VERSION 5.7 ;
  NOWIREEXTENSIONATPIN ON ;
  DIVIDERCHAR "/" ;
  BUSBITCHARS "[]" ;
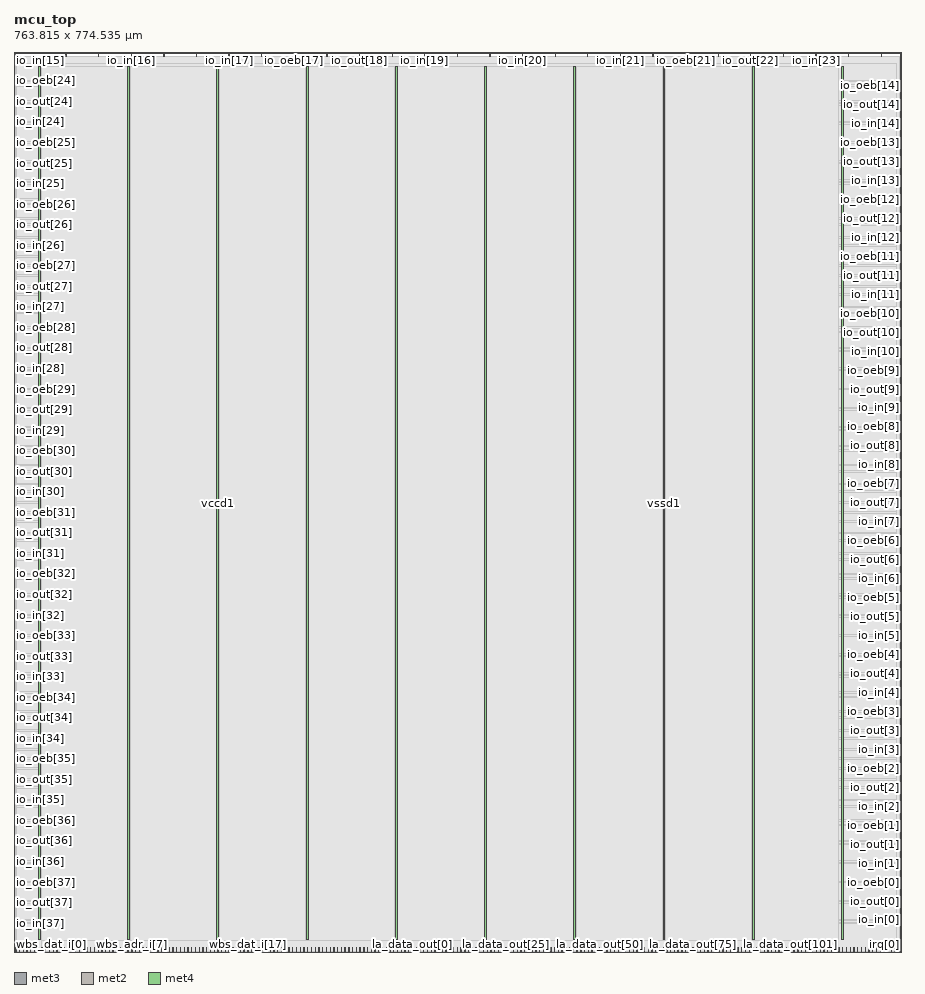
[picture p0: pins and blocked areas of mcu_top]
MACRO mcu_top
  CLASS BLOCK ;
  FOREIGN mcu_top ;
  ORIGIN 0.000 0.000 ;
  SIZE 763.815 BY 774.535 ;
  PIN io_in[0]
    DIRECTION INPUT ;
    USE SIGNAL ;
    PORT
      LAYER met3 ;
        RECT 759.815 27.240 763.815 27.840 ;
    END
  END io_in[0]
  PIN io_in[10]
    DIRECTION INPUT ;
    USE SIGNAL ;
    ANTENNAGATEAREA 0.213000 ;
    PORT
      LAYER met3 ;
        RECT 759.815 516.840 763.815 517.440 ;
    END
  END io_in[10]
  PIN io_in[11]
    DIRECTION INPUT ;
    USE SIGNAL ;
    ANTENNAGATEAREA 0.247500 ;
    PORT
      LAYER met3 ;
        RECT 759.815 565.800 763.815 566.400 ;
    END
  END io_in[11]
  PIN io_in[12]
    DIRECTION INPUT ;
    USE SIGNAL ;
    ANTENNAGATEAREA 0.247500 ;
    PORT
      LAYER met3 ;
        RECT 759.815 614.760 763.815 615.360 ;
    END
  END io_in[12]
  PIN io_in[13]
    DIRECTION INPUT ;
    USE SIGNAL ;
    ANTENNAGATEAREA 0.247500 ;
    PORT
      LAYER met3 ;
        RECT 759.815 663.720 763.815 664.320 ;
    END
  END io_in[13]
  PIN io_in[14]
    DIRECTION INPUT ;
    USE SIGNAL ;
    ANTENNAGATEAREA 0.247500 ;
    PORT
      LAYER met3 ;
        RECT 759.815 712.680 763.815 713.280 ;
    END
  END io_in[14]
  PIN io_in[15]
    DIRECTION INPUT ;
    USE SIGNAL ;
    ANTENNAGATEAREA 0.247500 ;
    PORT
      LAYER met2 ;
        RECT 16.650 770.535 16.930 774.535 ;
    END
  END io_in[15]
  PIN io_in[16]
    DIRECTION INPUT ;
    USE SIGNAL ;
    ANTENNAGATEAREA 0.247500 ;
    PORT
      LAYER met2 ;
        RECT 100.830 770.535 101.110 774.535 ;
    END
  END io_in[16]
  PIN io_in[17]
    DIRECTION INPUT ;
    USE SIGNAL ;
    ANTENNAGATEAREA 0.247500 ;
    PORT
      LAYER met2 ;
        RECT 185.010 770.535 185.290 774.535 ;
    END
  END io_in[17]
  PIN io_in[18]
    DIRECTION INPUT ;
    USE SIGNAL ;
    ANTENNAGATEAREA 0.213000 ;
    PORT
      LAYER met2 ;
        RECT 269.190 770.535 269.470 774.535 ;
    END
  END io_in[18]
  PIN io_in[19]
    DIRECTION INPUT ;
    USE SIGNAL ;
    ANTENNAGATEAREA 0.213000 ;
    PORT
      LAYER met2 ;
        RECT 353.370 770.535 353.650 774.535 ;
    END
  END io_in[19]
  PIN io_in[1]
    DIRECTION INPUT ;
    USE SIGNAL ;
    PORT
      LAYER met3 ;
        RECT 759.815 76.200 763.815 76.800 ;
    END
  END io_in[1]
  PIN io_in[20]
    DIRECTION INPUT ;
    USE SIGNAL ;
    ANTENNAGATEAREA 0.213000 ;
    PORT
      LAYER met2 ;
        RECT 437.550 770.535 437.830 774.535 ;
    END
  END io_in[20]
  PIN io_in[21]
    DIRECTION INPUT ;
    USE SIGNAL ;
    ANTENNAGATEAREA 0.213000 ;
    PORT
      LAYER met2 ;
        RECT 521.730 770.535 522.010 774.535 ;
    END
  END io_in[21]
  PIN io_in[22]
    DIRECTION INPUT ;
    USE SIGNAL ;
    ANTENNAGATEAREA 0.247500 ;
    PORT
      LAYER met2 ;
        RECT 605.910 770.535 606.190 774.535 ;
    END
  END io_in[22]
  PIN io_in[23]
    DIRECTION INPUT ;
    USE SIGNAL ;
    ANTENNAGATEAREA 0.247500 ;
    PORT
      LAYER met2 ;
        RECT 690.090 770.535 690.370 774.535 ;
    END
  END io_in[23]
  PIN io_in[24]
    DIRECTION INPUT ;
    USE SIGNAL ;
    ANTENNAGATEAREA 0.247500 ;
    PORT
      LAYER met3 ;
        RECT 0.000 714.040 4.000 714.640 ;
    END
  END io_in[24]
  PIN io_in[25]
    DIRECTION INPUT ;
    USE SIGNAL ;
    ANTENNAGATEAREA 0.247500 ;
    PORT
      LAYER met3 ;
        RECT 0.000 661.000 4.000 661.600 ;
    END
  END io_in[25]
  PIN io_in[26]
    DIRECTION INPUT ;
    USE SIGNAL ;
    PORT
      LAYER met3 ;
        RECT 0.000 607.960 4.000 608.560 ;
    END
  END io_in[26]
  PIN io_in[27]
    DIRECTION INPUT ;
    USE SIGNAL ;
    PORT
      LAYER met3 ;
        RECT 0.000 554.920 4.000 555.520 ;
    END
  END io_in[27]
  PIN io_in[28]
    DIRECTION INPUT ;
    USE SIGNAL ;
    PORT
      LAYER met3 ;
        RECT 0.000 501.880 4.000 502.480 ;
    END
  END io_in[28]
  PIN io_in[29]
    DIRECTION INPUT ;
    USE SIGNAL ;
    PORT
      LAYER met3 ;
        RECT 0.000 448.840 4.000 449.440 ;
    END
  END io_in[29]
  PIN io_in[2]
    DIRECTION INPUT ;
    USE SIGNAL ;
    PORT
      LAYER met3 ;
        RECT 759.815 125.160 763.815 125.760 ;
    END
  END io_in[2]
  PIN io_in[30]
    DIRECTION INPUT ;
    USE SIGNAL ;
    PORT
      LAYER met3 ;
        RECT 0.000 395.800 4.000 396.400 ;
    END
  END io_in[30]
  PIN io_in[31]
    DIRECTION INPUT ;
    USE SIGNAL ;
    PORT
      LAYER met3 ;
        RECT 0.000 342.760 4.000 343.360 ;
    END
  END io_in[31]
  PIN io_in[32]
    DIRECTION INPUT ;
    USE SIGNAL ;
    PORT
      LAYER met3 ;
        RECT 0.000 289.720 4.000 290.320 ;
    END
  END io_in[32]
  PIN io_in[33]
    DIRECTION INPUT ;
    USE SIGNAL ;
    PORT
      LAYER met3 ;
        RECT 0.000 236.680 4.000 237.280 ;
    END
  END io_in[33]
  PIN io_in[34]
    DIRECTION INPUT ;
    USE SIGNAL ;
    PORT
      LAYER met3 ;
        RECT 0.000 183.640 4.000 184.240 ;
    END
  END io_in[34]
  PIN io_in[35]
    DIRECTION INPUT ;
    USE SIGNAL ;
    PORT
      LAYER met3 ;
        RECT 0.000 130.600 4.000 131.200 ;
    END
  END io_in[35]
  PIN io_in[36]
    DIRECTION INPUT ;
    USE SIGNAL ;
    PORT
      LAYER met3 ;
        RECT 0.000 77.560 4.000 78.160 ;
    END
  END io_in[36]
  PIN io_in[37]
    DIRECTION INPUT ;
    USE SIGNAL ;
    PORT
      LAYER met3 ;
        RECT 0.000 24.520 4.000 25.120 ;
    END
  END io_in[37]
  PIN io_in[3]
    DIRECTION INPUT ;
    USE SIGNAL ;
    PORT
      LAYER met3 ;
        RECT 759.815 174.120 763.815 174.720 ;
    END
  END io_in[3]
  PIN io_in[4]
    DIRECTION INPUT ;
    USE SIGNAL ;
    PORT
      LAYER met3 ;
        RECT 759.815 223.080 763.815 223.680 ;
    END
  END io_in[4]
  PIN io_in[5]
    DIRECTION INPUT ;
    USE SIGNAL ;
    PORT
      LAYER met3 ;
        RECT 759.815 272.040 763.815 272.640 ;
    END
  END io_in[5]
  PIN io_in[6]
    DIRECTION INPUT ;
    USE SIGNAL ;
    PORT
      LAYER met3 ;
        RECT 759.815 321.000 763.815 321.600 ;
    END
  END io_in[6]
  PIN io_in[7]
    DIRECTION INPUT ;
    USE SIGNAL ;
    PORT
      LAYER met3 ;
        RECT 759.815 369.960 763.815 370.560 ;
    END
  END io_in[7]
  PIN io_in[8]
    DIRECTION INPUT ;
    USE SIGNAL ;
    PORT
      LAYER met3 ;
        RECT 759.815 418.920 763.815 419.520 ;
    END
  END io_in[8]
  PIN io_in[9]
    DIRECTION INPUT ;
    USE SIGNAL ;
    ANTENNAGATEAREA 0.247500 ;
    PORT
      LAYER met3 ;
        RECT 759.815 467.880 763.815 468.480 ;
    END
  END io_in[9]
  PIN io_oeb[0]
    DIRECTION OUTPUT ;
    USE SIGNAL ;
    PORT
      LAYER met3 ;
        RECT 759.815 59.880 763.815 60.480 ;
    END
  END io_oeb[0]
  PIN io_oeb[10]
    DIRECTION OUTPUT ;
    USE SIGNAL ;
    ANTENNADIFFAREA 2.673000 ;
    PORT
      LAYER met3 ;
        RECT 759.815 549.480 763.815 550.080 ;
    END
  END io_oeb[10]
  PIN io_oeb[11]
    DIRECTION OUTPUT ;
    USE SIGNAL ;
    ANTENNADIFFAREA 2.673000 ;
    PORT
      LAYER met3 ;
        RECT 759.815 598.440 763.815 599.040 ;
    END
  END io_oeb[11]
  PIN io_oeb[12]
    DIRECTION OUTPUT ;
    USE SIGNAL ;
    ANTENNADIFFAREA 2.673000 ;
    PORT
      LAYER met3 ;
        RECT 759.815 647.400 763.815 648.000 ;
    END
  END io_oeb[12]
  PIN io_oeb[13]
    DIRECTION OUTPUT ;
    USE SIGNAL ;
    ANTENNADIFFAREA 2.673000 ;
    PORT
      LAYER met3 ;
        RECT 759.815 696.360 763.815 696.960 ;
    END
  END io_oeb[13]
  PIN io_oeb[14]
    DIRECTION OUTPUT ;
    USE SIGNAL ;
    ANTENNADIFFAREA 2.673000 ;
    PORT
      LAYER met3 ;
        RECT 759.815 745.320 763.815 745.920 ;
    END
  END io_oeb[14]
  PIN io_oeb[15]
    DIRECTION OUTPUT ;
    USE SIGNAL ;
    ANTENNADIFFAREA 2.673000 ;
    PORT
      LAYER met2 ;
        RECT 72.770 770.535 73.050 774.535 ;
    END
  END io_oeb[15]
  PIN io_oeb[16]
    DIRECTION OUTPUT ;
    USE SIGNAL ;
    ANTENNADIFFAREA 2.673000 ;
    PORT
      LAYER met2 ;
        RECT 156.950 770.535 157.230 774.535 ;
    END
  END io_oeb[16]
  PIN io_oeb[17]
    DIRECTION OUTPUT ;
    USE SIGNAL ;
    ANTENNADIFFAREA 2.673000 ;
    PORT
      LAYER met2 ;
        RECT 241.130 770.535 241.410 774.535 ;
    END
  END io_oeb[17]
  PIN io_oeb[18]
    DIRECTION OUTPUT ;
    USE SIGNAL ;
    ANTENNADIFFAREA 2.673000 ;
    PORT
      LAYER met2 ;
        RECT 325.310 770.535 325.590 774.535 ;
    END
  END io_oeb[18]
  PIN io_oeb[19]
    DIRECTION OUTPUT ;
    USE SIGNAL ;
    ANTENNADIFFAREA 2.673000 ;
    PORT
      LAYER met2 ;
        RECT 409.490 770.535 409.770 774.535 ;
    END
  END io_oeb[19]
  PIN io_oeb[1]
    DIRECTION OUTPUT ;
    USE SIGNAL ;
    PORT
      LAYER met3 ;
        RECT 759.815 108.840 763.815 109.440 ;
    END
  END io_oeb[1]
  PIN io_oeb[20]
    DIRECTION OUTPUT ;
    USE SIGNAL ;
    ANTENNADIFFAREA 2.673000 ;
    PORT
      LAYER met2 ;
        RECT 493.670 770.535 493.950 774.535 ;
    END
  END io_oeb[20]
  PIN io_oeb[21]
    DIRECTION OUTPUT ;
    USE SIGNAL ;
    ANTENNADIFFAREA 2.673000 ;
    PORT
      LAYER met2 ;
        RECT 577.850 770.535 578.130 774.535 ;
    END
  END io_oeb[21]
  PIN io_oeb[22]
    DIRECTION OUTPUT ;
    USE SIGNAL ;
    ANTENNADIFFAREA 2.673000 ;
    PORT
      LAYER met2 ;
        RECT 662.030 770.535 662.310 774.535 ;
    END
  END io_oeb[22]
  PIN io_oeb[23]
    DIRECTION OUTPUT ;
    USE SIGNAL ;
    ANTENNADIFFAREA 2.673000 ;
    PORT
      LAYER met2 ;
        RECT 746.210 770.535 746.490 774.535 ;
    END
  END io_oeb[23]
  PIN io_oeb[24]
    DIRECTION OUTPUT ;
    USE SIGNAL ;
    ANTENNADIFFAREA 2.673000 ;
    PORT
      LAYER met3 ;
        RECT 0.000 749.400 4.000 750.000 ;
    END
  END io_oeb[24]
  PIN io_oeb[25]
    DIRECTION OUTPUT ;
    USE SIGNAL ;
    ANTENNADIFFAREA 2.673000 ;
    PORT
      LAYER met3 ;
        RECT 0.000 696.360 4.000 696.960 ;
    END
  END io_oeb[25]
  PIN io_oeb[26]
    DIRECTION OUTPUT ;
    USE SIGNAL ;
    PORT
      LAYER met3 ;
        RECT 0.000 643.320 4.000 643.920 ;
    END
  END io_oeb[26]
  PIN io_oeb[27]
    DIRECTION OUTPUT ;
    USE SIGNAL ;
    PORT
      LAYER met3 ;
        RECT 0.000 590.280 4.000 590.880 ;
    END
  END io_oeb[27]
  PIN io_oeb[28]
    DIRECTION OUTPUT ;
    USE SIGNAL ;
    PORT
      LAYER met3 ;
        RECT 0.000 537.240 4.000 537.840 ;
    END
  END io_oeb[28]
  PIN io_oeb[29]
    DIRECTION OUTPUT ;
    USE SIGNAL ;
    PORT
      LAYER met3 ;
        RECT 0.000 484.200 4.000 484.800 ;
    END
  END io_oeb[29]
  PIN io_oeb[2]
    DIRECTION OUTPUT ;
    USE SIGNAL ;
    PORT
      LAYER met3 ;
        RECT 759.815 157.800 763.815 158.400 ;
    END
  END io_oeb[2]
  PIN io_oeb[30]
    DIRECTION OUTPUT ;
    USE SIGNAL ;
    PORT
      LAYER met3 ;
        RECT 0.000 431.160 4.000 431.760 ;
    END
  END io_oeb[30]
  PIN io_oeb[31]
    DIRECTION OUTPUT ;
    USE SIGNAL ;
    PORT
      LAYER met3 ;
        RECT 0.000 378.120 4.000 378.720 ;
    END
  END io_oeb[31]
  PIN io_oeb[32]
    DIRECTION OUTPUT ;
    USE SIGNAL ;
    PORT
      LAYER met3 ;
        RECT 0.000 325.080 4.000 325.680 ;
    END
  END io_oeb[32]
  PIN io_oeb[33]
    DIRECTION OUTPUT ;
    USE SIGNAL ;
    PORT
      LAYER met3 ;
        RECT 0.000 272.040 4.000 272.640 ;
    END
  END io_oeb[33]
  PIN io_oeb[34]
    DIRECTION OUTPUT ;
    USE SIGNAL ;
    PORT
      LAYER met3 ;
        RECT 0.000 219.000 4.000 219.600 ;
    END
  END io_oeb[34]
  PIN io_oeb[35]
    DIRECTION OUTPUT ;
    USE SIGNAL ;
    PORT
      LAYER met3 ;
        RECT 0.000 165.960 4.000 166.560 ;
    END
  END io_oeb[35]
  PIN io_oeb[36]
    DIRECTION OUTPUT ;
    USE SIGNAL ;
    PORT
      LAYER met3 ;
        RECT 0.000 112.920 4.000 113.520 ;
    END
  END io_oeb[36]
  PIN io_oeb[37]
    DIRECTION OUTPUT ;
    USE SIGNAL ;
    PORT
      LAYER met3 ;
        RECT 0.000 59.880 4.000 60.480 ;
    END
  END io_oeb[37]
  PIN io_oeb[3]
    DIRECTION OUTPUT ;
    USE SIGNAL ;
    PORT
      LAYER met3 ;
        RECT 759.815 206.760 763.815 207.360 ;
    END
  END io_oeb[3]
  PIN io_oeb[4]
    DIRECTION OUTPUT ;
    USE SIGNAL ;
    PORT
      LAYER met3 ;
        RECT 759.815 255.720 763.815 256.320 ;
    END
  END io_oeb[4]
  PIN io_oeb[5]
    DIRECTION OUTPUT ;
    USE SIGNAL ;
    PORT
      LAYER met3 ;
        RECT 759.815 304.680 763.815 305.280 ;
    END
  END io_oeb[5]
  PIN io_oeb[6]
    DIRECTION OUTPUT ;
    USE SIGNAL ;
    PORT
      LAYER met3 ;
        RECT 759.815 353.640 763.815 354.240 ;
    END
  END io_oeb[6]
  PIN io_oeb[7]
    DIRECTION OUTPUT ;
    USE SIGNAL ;
    PORT
      LAYER met3 ;
        RECT 759.815 402.600 763.815 403.200 ;
    END
  END io_oeb[7]
  PIN io_oeb[8]
    DIRECTION OUTPUT ;
    USE SIGNAL ;
    PORT
      LAYER met3 ;
        RECT 759.815 451.560 763.815 452.160 ;
    END
  END io_oeb[8]
  PIN io_oeb[9]
    DIRECTION OUTPUT ;
    USE SIGNAL ;
    PORT
      LAYER met3 ;
        RECT 759.815 500.520 763.815 501.120 ;
    END
  END io_oeb[9]
  PIN io_out[0]
    DIRECTION OUTPUT ;
    USE SIGNAL ;
    PORT
      LAYER met3 ;
        RECT 759.815 43.560 763.815 44.160 ;
    END
  END io_out[0]
  PIN io_out[10]
    DIRECTION OUTPUT ;
    USE SIGNAL ;
    ANTENNADIFFAREA 2.673000 ;
    PORT
      LAYER met3 ;
        RECT 759.815 533.160 763.815 533.760 ;
    END
  END io_out[10]
  PIN io_out[11]
    DIRECTION OUTPUT ;
    USE SIGNAL ;
    ANTENNADIFFAREA 2.673000 ;
    PORT
      LAYER met3 ;
        RECT 759.815 582.120 763.815 582.720 ;
    END
  END io_out[11]
  PIN io_out[12]
    DIRECTION OUTPUT ;
    USE SIGNAL ;
    ANTENNADIFFAREA 2.673000 ;
    PORT
      LAYER met3 ;
        RECT 759.815 631.080 763.815 631.680 ;
    END
  END io_out[12]
  PIN io_out[13]
    DIRECTION OUTPUT ;
    USE SIGNAL ;
    ANTENNADIFFAREA 2.673000 ;
    PORT
      LAYER met3 ;
        RECT 759.815 680.040 763.815 680.640 ;
    END
  END io_out[13]
  PIN io_out[14]
    DIRECTION OUTPUT ;
    USE SIGNAL ;
    ANTENNADIFFAREA 2.673000 ;
    PORT
      LAYER met3 ;
        RECT 759.815 729.000 763.815 729.600 ;
    END
  END io_out[14]
  PIN io_out[15]
    DIRECTION OUTPUT ;
    USE SIGNAL ;
    ANTENNADIFFAREA 2.673000 ;
    PORT
      LAYER met2 ;
        RECT 44.710 770.535 44.990 774.535 ;
    END
  END io_out[15]
  PIN io_out[16]
    DIRECTION OUTPUT ;
    USE SIGNAL ;
    ANTENNADIFFAREA 2.673000 ;
    PORT
      LAYER met2 ;
        RECT 128.890 770.535 129.170 774.535 ;
    END
  END io_out[16]
  PIN io_out[17]
    DIRECTION OUTPUT ;
    USE SIGNAL ;
    ANTENNADIFFAREA 2.673000 ;
    PORT
      LAYER met2 ;
        RECT 213.070 770.535 213.350 774.535 ;
    END
  END io_out[17]
  PIN io_out[18]
    DIRECTION OUTPUT ;
    USE SIGNAL ;
    ANTENNADIFFAREA 2.673000 ;
    PORT
      LAYER met2 ;
        RECT 297.250 770.535 297.530 774.535 ;
    END
  END io_out[18]
  PIN io_out[19]
    DIRECTION OUTPUT ;
    USE SIGNAL ;
    ANTENNADIFFAREA 2.673000 ;
    PORT
      LAYER met2 ;
        RECT 381.430 770.535 381.710 774.535 ;
    END
  END io_out[19]
  PIN io_out[1]
    DIRECTION OUTPUT ;
    USE SIGNAL ;
    PORT
      LAYER met3 ;
        RECT 759.815 92.520 763.815 93.120 ;
    END
  END io_out[1]
  PIN io_out[20]
    DIRECTION OUTPUT ;
    USE SIGNAL ;
    ANTENNADIFFAREA 2.673000 ;
    PORT
      LAYER met2 ;
        RECT 465.610 770.535 465.890 774.535 ;
    END
  END io_out[20]
  PIN io_out[21]
    DIRECTION OUTPUT ;
    USE SIGNAL ;
    ANTENNADIFFAREA 2.673000 ;
    PORT
      LAYER met2 ;
        RECT 549.790 770.535 550.070 774.535 ;
    END
  END io_out[21]
  PIN io_out[22]
    DIRECTION OUTPUT ;
    USE SIGNAL ;
    ANTENNADIFFAREA 2.673000 ;
    PORT
      LAYER met2 ;
        RECT 633.970 770.535 634.250 774.535 ;
    END
  END io_out[22]
  PIN io_out[23]
    DIRECTION OUTPUT ;
    USE SIGNAL ;
    ANTENNADIFFAREA 2.673000 ;
    PORT
      LAYER met2 ;
        RECT 718.150 770.535 718.430 774.535 ;
    END
  END io_out[23]
  PIN io_out[24]
    DIRECTION OUTPUT ;
    USE SIGNAL ;
    ANTENNADIFFAREA 2.673000 ;
    PORT
      LAYER met3 ;
        RECT 0.000 731.720 4.000 732.320 ;
    END
  END io_out[24]
  PIN io_out[25]
    DIRECTION OUTPUT ;
    USE SIGNAL ;
    ANTENNADIFFAREA 2.673000 ;
    PORT
      LAYER met3 ;
        RECT 0.000 678.680 4.000 679.280 ;
    END
  END io_out[25]
  PIN io_out[26]
    DIRECTION OUTPUT ;
    USE SIGNAL ;
    PORT
      LAYER met3 ;
        RECT 0.000 625.640 4.000 626.240 ;
    END
  END io_out[26]
  PIN io_out[27]
    DIRECTION OUTPUT ;
    USE SIGNAL ;
    PORT
      LAYER met3 ;
        RECT 0.000 572.600 4.000 573.200 ;
    END
  END io_out[27]
  PIN io_out[28]
    DIRECTION OUTPUT ;
    USE SIGNAL ;
    PORT
      LAYER met3 ;
        RECT 0.000 519.560 4.000 520.160 ;
    END
  END io_out[28]
  PIN io_out[29]
    DIRECTION OUTPUT ;
    USE SIGNAL ;
    PORT
      LAYER met3 ;
        RECT 0.000 466.520 4.000 467.120 ;
    END
  END io_out[29]
  PIN io_out[2]
    DIRECTION OUTPUT ;
    USE SIGNAL ;
    PORT
      LAYER met3 ;
        RECT 759.815 141.480 763.815 142.080 ;
    END
  END io_out[2]
  PIN io_out[30]
    DIRECTION OUTPUT ;
    USE SIGNAL ;
    PORT
      LAYER met3 ;
        RECT 0.000 413.480 4.000 414.080 ;
    END
  END io_out[30]
  PIN io_out[31]
    DIRECTION OUTPUT ;
    USE SIGNAL ;
    PORT
      LAYER met3 ;
        RECT 0.000 360.440 4.000 361.040 ;
    END
  END io_out[31]
  PIN io_out[32]
    DIRECTION OUTPUT ;
    USE SIGNAL ;
    PORT
      LAYER met3 ;
        RECT 0.000 307.400 4.000 308.000 ;
    END
  END io_out[32]
  PIN io_out[33]
    DIRECTION OUTPUT ;
    USE SIGNAL ;
    PORT
      LAYER met3 ;
        RECT 0.000 254.360 4.000 254.960 ;
    END
  END io_out[33]
  PIN io_out[34]
    DIRECTION OUTPUT ;
    USE SIGNAL ;
    PORT
      LAYER met3 ;
        RECT 0.000 201.320 4.000 201.920 ;
    END
  END io_out[34]
  PIN io_out[35]
    DIRECTION OUTPUT ;
    USE SIGNAL ;
    PORT
      LAYER met3 ;
        RECT 0.000 148.280 4.000 148.880 ;
    END
  END io_out[35]
  PIN io_out[36]
    DIRECTION OUTPUT ;
    USE SIGNAL ;
    PORT
      LAYER met3 ;
        RECT 0.000 95.240 4.000 95.840 ;
    END
  END io_out[36]
  PIN io_out[37]
    DIRECTION OUTPUT ;
    USE SIGNAL ;
    PORT
      LAYER met3 ;
        RECT 0.000 42.200 4.000 42.800 ;
    END
  END io_out[37]
  PIN io_out[3]
    DIRECTION OUTPUT ;
    USE SIGNAL ;
    PORT
      LAYER met3 ;
        RECT 759.815 190.440 763.815 191.040 ;
    END
  END io_out[3]
  PIN io_out[4]
    DIRECTION OUTPUT ;
    USE SIGNAL ;
    PORT
      LAYER met3 ;
        RECT 759.815 239.400 763.815 240.000 ;
    END
  END io_out[4]
  PIN io_out[5]
    DIRECTION OUTPUT ;
    USE SIGNAL ;
    PORT
      LAYER met3 ;
        RECT 759.815 288.360 763.815 288.960 ;
    END
  END io_out[5]
  PIN io_out[6]
    DIRECTION OUTPUT ;
    USE SIGNAL ;
    PORT
      LAYER met3 ;
        RECT 759.815 337.320 763.815 337.920 ;
    END
  END io_out[6]
  PIN io_out[7]
    DIRECTION OUTPUT ;
    USE SIGNAL ;
    PORT
      LAYER met3 ;
        RECT 759.815 386.280 763.815 386.880 ;
    END
  END io_out[7]
  PIN io_out[8]
    DIRECTION OUTPUT ;
    USE SIGNAL ;
    ANTENNADIFFAREA 2.673000 ;
    PORT
      LAYER met3 ;
        RECT 759.815 435.240 763.815 435.840 ;
    END
  END io_out[8]
  PIN io_out[9]
    DIRECTION OUTPUT ;
    USE SIGNAL ;
    PORT
      LAYER met3 ;
        RECT 759.815 484.200 763.815 484.800 ;
    END
  END io_out[9]
  PIN irq[0]
    DIRECTION OUTPUT ;
    USE SIGNAL ;
    ANTENNADIFFAREA 2.673000 ;
    PORT
      LAYER met2 ;
        RECT 754.950 0.000 755.230 4.000 ;
    END
  END irq[0]
  PIN irq[1]
    DIRECTION OUTPUT ;
    USE SIGNAL ;
    PORT
      LAYER met2 ;
        RECT 758.170 0.000 758.450 4.000 ;
    END
  END irq[1]
  PIN irq[2]
    DIRECTION OUTPUT ;
    USE SIGNAL ;
    PORT
      LAYER met2 ;
        RECT 761.390 0.000 761.670 4.000 ;
    END
  END irq[2]
  PIN la_data_out[0]
    DIRECTION OUTPUT ;
    USE SIGNAL ;
    PORT
      LAYER met2 ;
        RECT 342.790 0.000 343.070 4.000 ;
    END
  END la_data_out[0]
  PIN la_data_out[100]
    DIRECTION OUTPUT ;
    USE SIGNAL ;
    PORT
      LAYER met2 ;
        RECT 664.790 0.000 665.070 4.000 ;
    END
  END la_data_out[100]
  PIN la_data_out[101]
    DIRECTION OUTPUT ;
    USE SIGNAL ;
    PORT
      LAYER met2 ;
        RECT 668.010 0.000 668.290 4.000 ;
    END
  END la_data_out[101]
  PIN la_data_out[102]
    DIRECTION OUTPUT ;
    USE SIGNAL ;
    PORT
      LAYER met2 ;
        RECT 671.230 0.000 671.510 4.000 ;
    END
  END la_data_out[102]
  PIN la_data_out[103]
    DIRECTION OUTPUT ;
    USE SIGNAL ;
    PORT
      LAYER met2 ;
        RECT 674.450 0.000 674.730 4.000 ;
    END
  END la_data_out[103]
  PIN la_data_out[104]
    DIRECTION OUTPUT ;
    USE SIGNAL ;
    PORT
      LAYER met2 ;
        RECT 677.670 0.000 677.950 4.000 ;
    END
  END la_data_out[104]
  PIN la_data_out[105]
    DIRECTION OUTPUT ;
    USE SIGNAL ;
    PORT
      LAYER met2 ;
        RECT 680.890 0.000 681.170 4.000 ;
    END
  END la_data_out[105]
  PIN la_data_out[106]
    DIRECTION OUTPUT ;
    USE SIGNAL ;
    PORT
      LAYER met2 ;
        RECT 684.110 0.000 684.390 4.000 ;
    END
  END la_data_out[106]
  PIN la_data_out[107]
    DIRECTION OUTPUT ;
    USE SIGNAL ;
    PORT
      LAYER met2 ;
        RECT 687.330 0.000 687.610 4.000 ;
    END
  END la_data_out[107]
  PIN la_data_out[108]
    DIRECTION OUTPUT ;
    USE SIGNAL ;
    PORT
      LAYER met2 ;
        RECT 690.550 0.000 690.830 4.000 ;
    END
  END la_data_out[108]
  PIN la_data_out[109]
    DIRECTION OUTPUT ;
    USE SIGNAL ;
    PORT
      LAYER met2 ;
        RECT 693.770 0.000 694.050 4.000 ;
    END
  END la_data_out[109]
  PIN la_data_out[10]
    DIRECTION OUTPUT ;
    USE SIGNAL ;
    ANTENNADIFFAREA 2.673000 ;
    PORT
      LAYER met2 ;
        RECT 374.990 0.000 375.270 4.000 ;
    END
  END la_data_out[10]
  PIN la_data_out[110]
    DIRECTION OUTPUT ;
    USE SIGNAL ;
    PORT
      LAYER met2 ;
        RECT 696.990 0.000 697.270 4.000 ;
    END
  END la_data_out[110]
  PIN la_data_out[111]
    DIRECTION OUTPUT ;
    USE SIGNAL ;
    PORT
      LAYER met2 ;
        RECT 700.210 0.000 700.490 4.000 ;
    END
  END la_data_out[111]
  PIN la_data_out[112]
    DIRECTION OUTPUT ;
    USE SIGNAL ;
    PORT
      LAYER met2 ;
        RECT 703.430 0.000 703.710 4.000 ;
    END
  END la_data_out[112]
  PIN la_data_out[113]
    DIRECTION OUTPUT ;
    USE SIGNAL ;
    PORT
      LAYER met2 ;
        RECT 706.650 0.000 706.930 4.000 ;
    END
  END la_data_out[113]
  PIN la_data_out[114]
    DIRECTION OUTPUT ;
    USE SIGNAL ;
    PORT
      LAYER met2 ;
        RECT 709.870 0.000 710.150 4.000 ;
    END
  END la_data_out[114]
  PIN la_data_out[115]
    DIRECTION OUTPUT ;
    USE SIGNAL ;
    PORT
      LAYER met2 ;
        RECT 713.090 0.000 713.370 4.000 ;
    END
  END la_data_out[115]
  PIN la_data_out[116]
    DIRECTION OUTPUT ;
    USE SIGNAL ;
    PORT
      LAYER met2 ;
        RECT 716.310 0.000 716.590 4.000 ;
    END
  END la_data_out[116]
  PIN la_data_out[117]
    DIRECTION OUTPUT ;
    USE SIGNAL ;
    PORT
      LAYER met2 ;
        RECT 719.530 0.000 719.810 4.000 ;
    END
  END la_data_out[117]
  PIN la_data_out[118]
    DIRECTION OUTPUT ;
    USE SIGNAL ;
    PORT
      LAYER met2 ;
        RECT 722.750 0.000 723.030 4.000 ;
    END
  END la_data_out[118]
  PIN la_data_out[119]
    DIRECTION OUTPUT ;
    USE SIGNAL ;
    PORT
      LAYER met2 ;
        RECT 725.970 0.000 726.250 4.000 ;
    END
  END la_data_out[119]
  PIN la_data_out[11]
    DIRECTION OUTPUT ;
    USE SIGNAL ;
    ANTENNADIFFAREA 2.673000 ;
    PORT
      LAYER met2 ;
        RECT 378.210 0.000 378.490 4.000 ;
    END
  END la_data_out[11]
  PIN la_data_out[120]
    DIRECTION OUTPUT ;
    USE SIGNAL ;
    PORT
      LAYER met2 ;
        RECT 729.190 0.000 729.470 4.000 ;
    END
  END la_data_out[120]
  PIN la_data_out[121]
    DIRECTION OUTPUT ;
    USE SIGNAL ;
    PORT
      LAYER met2 ;
        RECT 732.410 0.000 732.690 4.000 ;
    END
  END la_data_out[121]
  PIN la_data_out[122]
    DIRECTION OUTPUT ;
    USE SIGNAL ;
    PORT
      LAYER met2 ;
        RECT 735.630 0.000 735.910 4.000 ;
    END
  END la_data_out[122]
  PIN la_data_out[123]
    DIRECTION OUTPUT ;
    USE SIGNAL ;
    PORT
      LAYER met2 ;
        RECT 738.850 0.000 739.130 4.000 ;
    END
  END la_data_out[123]
  PIN la_data_out[124]
    DIRECTION OUTPUT ;
    USE SIGNAL ;
    PORT
      LAYER met2 ;
        RECT 742.070 0.000 742.350 4.000 ;
    END
  END la_data_out[124]
  PIN la_data_out[125]
    DIRECTION OUTPUT ;
    USE SIGNAL ;
    PORT
      LAYER met2 ;
        RECT 745.290 0.000 745.570 4.000 ;
    END
  END la_data_out[125]
  PIN la_data_out[126]
    DIRECTION OUTPUT ;
    USE SIGNAL ;
    PORT
      LAYER met2 ;
        RECT 748.510 0.000 748.790 4.000 ;
    END
  END la_data_out[126]
  PIN la_data_out[127]
    DIRECTION OUTPUT ;
    USE SIGNAL ;
    PORT
      LAYER met2 ;
        RECT 751.730 0.000 752.010 4.000 ;
    END
  END la_data_out[127]
  PIN la_data_out[12]
    DIRECTION OUTPUT ;
    USE SIGNAL ;
    ANTENNADIFFAREA 2.673000 ;
    PORT
      LAYER met2 ;
        RECT 381.430 0.000 381.710 4.000 ;
    END
  END la_data_out[12]
  PIN la_data_out[13]
    DIRECTION OUTPUT ;
    USE SIGNAL ;
    ANTENNADIFFAREA 2.673000 ;
    PORT
      LAYER met2 ;
        RECT 384.650 0.000 384.930 4.000 ;
    END
  END la_data_out[13]
  PIN la_data_out[14]
    DIRECTION OUTPUT ;
    USE SIGNAL ;
    ANTENNADIFFAREA 2.673000 ;
    PORT
      LAYER met2 ;
        RECT 387.870 0.000 388.150 4.000 ;
    END
  END la_data_out[14]
  PIN la_data_out[15]
    DIRECTION OUTPUT ;
    USE SIGNAL ;
    ANTENNADIFFAREA 2.673000 ;
    PORT
      LAYER met2 ;
        RECT 391.090 0.000 391.370 4.000 ;
    END
  END la_data_out[15]
  PIN la_data_out[16]
    DIRECTION OUTPUT ;
    USE SIGNAL ;
    ANTENNADIFFAREA 2.673000 ;
    PORT
      LAYER met2 ;
        RECT 394.310 0.000 394.590 4.000 ;
    END
  END la_data_out[16]
  PIN la_data_out[17]
    DIRECTION OUTPUT ;
    USE SIGNAL ;
    ANTENNADIFFAREA 2.673000 ;
    PORT
      LAYER met2 ;
        RECT 397.530 0.000 397.810 4.000 ;
    END
  END la_data_out[17]
  PIN la_data_out[18]
    DIRECTION OUTPUT ;
    USE SIGNAL ;
    ANTENNADIFFAREA 2.673000 ;
    PORT
      LAYER met2 ;
        RECT 400.750 0.000 401.030 4.000 ;
    END
  END la_data_out[18]
  PIN la_data_out[19]
    DIRECTION OUTPUT ;
    USE SIGNAL ;
    ANTENNADIFFAREA 2.673000 ;
    PORT
      LAYER met2 ;
        RECT 403.970 0.000 404.250 4.000 ;
    END
  END la_data_out[19]
  PIN la_data_out[1]
    DIRECTION OUTPUT ;
    USE SIGNAL ;
    ANTENNADIFFAREA 2.673000 ;
    PORT
      LAYER met2 ;
        RECT 346.010 0.000 346.290 4.000 ;
    END
  END la_data_out[1]
  PIN la_data_out[20]
    DIRECTION OUTPUT ;
    USE SIGNAL ;
    ANTENNADIFFAREA 2.673000 ;
    PORT
      LAYER met2 ;
        RECT 407.190 0.000 407.470 4.000 ;
    END
  END la_data_out[20]
  PIN la_data_out[21]
    DIRECTION OUTPUT ;
    USE SIGNAL ;
    ANTENNADIFFAREA 2.673000 ;
    PORT
      LAYER met2 ;
        RECT 410.410 0.000 410.690 4.000 ;
    END
  END la_data_out[21]
  PIN la_data_out[22]
    DIRECTION OUTPUT ;
    USE SIGNAL ;
    ANTENNADIFFAREA 2.673000 ;
    PORT
      LAYER met2 ;
        RECT 413.630 0.000 413.910 4.000 ;
    END
  END la_data_out[22]
  PIN la_data_out[23]
    DIRECTION OUTPUT ;
    USE SIGNAL ;
    ANTENNADIFFAREA 2.673000 ;
    PORT
      LAYER met2 ;
        RECT 416.850 0.000 417.130 4.000 ;
    END
  END la_data_out[23]
  PIN la_data_out[24]
    DIRECTION OUTPUT ;
    USE SIGNAL ;
    ANTENNADIFFAREA 2.673000 ;
    PORT
      LAYER met2 ;
        RECT 420.070 0.000 420.350 4.000 ;
    END
  END la_data_out[24]
  PIN la_data_out[25]
    DIRECTION OUTPUT ;
    USE SIGNAL ;
    ANTENNADIFFAREA 2.673000 ;
    PORT
      LAYER met2 ;
        RECT 423.290 0.000 423.570 4.000 ;
    END
  END la_data_out[25]
  PIN la_data_out[26]
    DIRECTION OUTPUT ;
    USE SIGNAL ;
    ANTENNADIFFAREA 2.673000 ;
    PORT
      LAYER met2 ;
        RECT 426.510 0.000 426.790 4.000 ;
    END
  END la_data_out[26]
  PIN la_data_out[27]
    DIRECTION OUTPUT ;
    USE SIGNAL ;
    ANTENNADIFFAREA 2.673000 ;
    PORT
      LAYER met2 ;
        RECT 429.730 0.000 430.010 4.000 ;
    END
  END la_data_out[27]
  PIN la_data_out[28]
    DIRECTION OUTPUT ;
    USE SIGNAL ;
    ANTENNADIFFAREA 2.673000 ;
    PORT
      LAYER met2 ;
        RECT 432.950 0.000 433.230 4.000 ;
    END
  END la_data_out[28]
  PIN la_data_out[29]
    DIRECTION OUTPUT ;
    USE SIGNAL ;
    ANTENNADIFFAREA 2.673000 ;
    PORT
      LAYER met2 ;
        RECT 436.170 0.000 436.450 4.000 ;
    END
  END la_data_out[29]
  PIN la_data_out[2]
    DIRECTION OUTPUT ;
    USE SIGNAL ;
    ANTENNADIFFAREA 2.673000 ;
    PORT
      LAYER met2 ;
        RECT 349.230 0.000 349.510 4.000 ;
    END
  END la_data_out[2]
  PIN la_data_out[30]
    DIRECTION OUTPUT ;
    USE SIGNAL ;
    ANTENNADIFFAREA 2.673000 ;
    PORT
      LAYER met2 ;
        RECT 439.390 0.000 439.670 4.000 ;
    END
  END la_data_out[30]
  PIN la_data_out[31]
    DIRECTION OUTPUT ;
    USE SIGNAL ;
    ANTENNADIFFAREA 2.673000 ;
    PORT
      LAYER met2 ;
        RECT 442.610 0.000 442.890 4.000 ;
    END
  END la_data_out[31]
  PIN la_data_out[32]
    DIRECTION OUTPUT ;
    USE SIGNAL ;
    ANTENNADIFFAREA 2.673000 ;
    PORT
      LAYER met2 ;
        RECT 445.830 0.000 446.110 4.000 ;
    END
  END la_data_out[32]
  PIN la_data_out[33]
    DIRECTION OUTPUT ;
    USE SIGNAL ;
    ANTENNADIFFAREA 2.673000 ;
    PORT
      LAYER met2 ;
        RECT 449.050 0.000 449.330 4.000 ;
    END
  END la_data_out[33]
  PIN la_data_out[34]
    DIRECTION OUTPUT ;
    USE SIGNAL ;
    ANTENNADIFFAREA 2.673000 ;
    PORT
      LAYER met2 ;
        RECT 452.270 0.000 452.550 4.000 ;
    END
  END la_data_out[34]
  PIN la_data_out[35]
    DIRECTION OUTPUT ;
    USE SIGNAL ;
    ANTENNADIFFAREA 2.673000 ;
    PORT
      LAYER met2 ;
        RECT 455.490 0.000 455.770 4.000 ;
    END
  END la_data_out[35]
  PIN la_data_out[36]
    DIRECTION OUTPUT ;
    USE SIGNAL ;
    ANTENNADIFFAREA 2.673000 ;
    PORT
      LAYER met2 ;
        RECT 458.710 0.000 458.990 4.000 ;
    END
  END la_data_out[36]
  PIN la_data_out[37]
    DIRECTION OUTPUT ;
    USE SIGNAL ;
    ANTENNADIFFAREA 2.673000 ;
    PORT
      LAYER met2 ;
        RECT 461.930 0.000 462.210 4.000 ;
    END
  END la_data_out[37]
  PIN la_data_out[38]
    DIRECTION OUTPUT ;
    USE SIGNAL ;
    ANTENNADIFFAREA 2.673000 ;
    PORT
      LAYER met2 ;
        RECT 465.150 0.000 465.430 4.000 ;
    END
  END la_data_out[38]
  PIN la_data_out[39]
    DIRECTION OUTPUT ;
    USE SIGNAL ;
    ANTENNADIFFAREA 2.673000 ;
    PORT
      LAYER met2 ;
        RECT 468.370 0.000 468.650 4.000 ;
    END
  END la_data_out[39]
  PIN la_data_out[3]
    DIRECTION OUTPUT ;
    USE SIGNAL ;
    ANTENNADIFFAREA 2.673000 ;
    PORT
      LAYER met2 ;
        RECT 352.450 0.000 352.730 4.000 ;
    END
  END la_data_out[3]
  PIN la_data_out[40]
    DIRECTION OUTPUT ;
    USE SIGNAL ;
    ANTENNADIFFAREA 2.673000 ;
    PORT
      LAYER met2 ;
        RECT 471.590 0.000 471.870 4.000 ;
    END
  END la_data_out[40]
  PIN la_data_out[41]
    DIRECTION OUTPUT ;
    USE SIGNAL ;
    ANTENNADIFFAREA 2.673000 ;
    PORT
      LAYER met2 ;
        RECT 474.810 0.000 475.090 4.000 ;
    END
  END la_data_out[41]
  PIN la_data_out[42]
    DIRECTION OUTPUT ;
    USE SIGNAL ;
    ANTENNADIFFAREA 2.673000 ;
    PORT
      LAYER met2 ;
        RECT 478.030 0.000 478.310 4.000 ;
    END
  END la_data_out[42]
  PIN la_data_out[43]
    DIRECTION OUTPUT ;
    USE SIGNAL ;
    ANTENNADIFFAREA 2.673000 ;
    PORT
      LAYER met2 ;
        RECT 481.250 0.000 481.530 4.000 ;
    END
  END la_data_out[43]
  PIN la_data_out[44]
    DIRECTION OUTPUT ;
    USE SIGNAL ;
    ANTENNADIFFAREA 2.673000 ;
    PORT
      LAYER met2 ;
        RECT 484.470 0.000 484.750 4.000 ;
    END
  END la_data_out[44]
  PIN la_data_out[45]
    DIRECTION OUTPUT ;
    USE SIGNAL ;
    ANTENNADIFFAREA 2.673000 ;
    PORT
      LAYER met2 ;
        RECT 487.690 0.000 487.970 4.000 ;
    END
  END la_data_out[45]
  PIN la_data_out[46]
    DIRECTION OUTPUT ;
    USE SIGNAL ;
    ANTENNADIFFAREA 2.673000 ;
    PORT
      LAYER met2 ;
        RECT 490.910 0.000 491.190 4.000 ;
    END
  END la_data_out[46]
  PIN la_data_out[47]
    DIRECTION OUTPUT ;
    USE SIGNAL ;
    ANTENNADIFFAREA 2.673000 ;
    PORT
      LAYER met2 ;
        RECT 494.130 0.000 494.410 4.000 ;
    END
  END la_data_out[47]
  PIN la_data_out[48]
    DIRECTION OUTPUT ;
    USE SIGNAL ;
    ANTENNADIFFAREA 2.673000 ;
    PORT
      LAYER met2 ;
        RECT 497.350 0.000 497.630 4.000 ;
    END
  END la_data_out[48]
  PIN la_data_out[49]
    DIRECTION OUTPUT ;
    USE SIGNAL ;
    ANTENNADIFFAREA 2.673000 ;
    PORT
      LAYER met2 ;
        RECT 500.570 0.000 500.850 4.000 ;
    END
  END la_data_out[49]
  PIN la_data_out[4]
    DIRECTION OUTPUT ;
    USE SIGNAL ;
    ANTENNADIFFAREA 2.673000 ;
    PORT
      LAYER met2 ;
        RECT 355.670 0.000 355.950 4.000 ;
    END
  END la_data_out[4]
  PIN la_data_out[50]
    DIRECTION OUTPUT ;
    USE SIGNAL ;
    ANTENNADIFFAREA 2.673000 ;
    PORT
      LAYER met2 ;
        RECT 503.790 0.000 504.070 4.000 ;
    END
  END la_data_out[50]
  PIN la_data_out[51]
    DIRECTION OUTPUT ;
    USE SIGNAL ;
    ANTENNADIFFAREA 2.673000 ;
    PORT
      LAYER met2 ;
        RECT 507.010 0.000 507.290 4.000 ;
    END
  END la_data_out[51]
  PIN la_data_out[52]
    DIRECTION OUTPUT ;
    USE SIGNAL ;
    ANTENNADIFFAREA 2.673000 ;
    PORT
      LAYER met2 ;
        RECT 510.230 0.000 510.510 4.000 ;
    END
  END la_data_out[52]
  PIN la_data_out[53]
    DIRECTION OUTPUT ;
    USE SIGNAL ;
    ANTENNADIFFAREA 2.673000 ;
    PORT
      LAYER met2 ;
        RECT 513.450 0.000 513.730 4.000 ;
    END
  END la_data_out[53]
  PIN la_data_out[54]
    DIRECTION OUTPUT ;
    USE SIGNAL ;
    ANTENNADIFFAREA 2.673000 ;
    PORT
      LAYER met2 ;
        RECT 516.670 0.000 516.950 4.000 ;
    END
  END la_data_out[54]
  PIN la_data_out[55]
    DIRECTION OUTPUT ;
    USE SIGNAL ;
    ANTENNADIFFAREA 2.673000 ;
    PORT
      LAYER met2 ;
        RECT 519.890 0.000 520.170 4.000 ;
    END
  END la_data_out[55]
  PIN la_data_out[56]
    DIRECTION OUTPUT ;
    USE SIGNAL ;
    ANTENNADIFFAREA 2.673000 ;
    PORT
      LAYER met2 ;
        RECT 523.110 0.000 523.390 4.000 ;
    END
  END la_data_out[56]
  PIN la_data_out[57]
    DIRECTION OUTPUT ;
    USE SIGNAL ;
    ANTENNADIFFAREA 2.673000 ;
    PORT
      LAYER met2 ;
        RECT 526.330 0.000 526.610 4.000 ;
    END
  END la_data_out[57]
  PIN la_data_out[58]
    DIRECTION OUTPUT ;
    USE SIGNAL ;
    ANTENNADIFFAREA 2.673000 ;
    PORT
      LAYER met2 ;
        RECT 529.550 0.000 529.830 4.000 ;
    END
  END la_data_out[58]
  PIN la_data_out[59]
    DIRECTION OUTPUT ;
    USE SIGNAL ;
    ANTENNADIFFAREA 2.673000 ;
    PORT
      LAYER met2 ;
        RECT 532.770 0.000 533.050 4.000 ;
    END
  END la_data_out[59]
  PIN la_data_out[5]
    DIRECTION OUTPUT ;
    USE SIGNAL ;
    ANTENNADIFFAREA 2.673000 ;
    PORT
      LAYER met2 ;
        RECT 358.890 0.000 359.170 4.000 ;
    END
  END la_data_out[5]
  PIN la_data_out[60]
    DIRECTION OUTPUT ;
    USE SIGNAL ;
    ANTENNADIFFAREA 2.673000 ;
    PORT
      LAYER met2 ;
        RECT 535.990 0.000 536.270 4.000 ;
    END
  END la_data_out[60]
  PIN la_data_out[61]
    DIRECTION OUTPUT ;
    USE SIGNAL ;
    ANTENNADIFFAREA 2.673000 ;
    PORT
      LAYER met2 ;
        RECT 539.210 0.000 539.490 4.000 ;
    END
  END la_data_out[61]
  PIN la_data_out[62]
    DIRECTION OUTPUT ;
    USE SIGNAL ;
    ANTENNADIFFAREA 2.673000 ;
    PORT
      LAYER met2 ;
        RECT 542.430 0.000 542.710 4.000 ;
    END
  END la_data_out[62]
  PIN la_data_out[63]
    DIRECTION OUTPUT ;
    USE SIGNAL ;
    ANTENNADIFFAREA 2.673000 ;
    PORT
      LAYER met2 ;
        RECT 545.650 0.000 545.930 4.000 ;
    END
  END la_data_out[63]
  PIN la_data_out[64]
    DIRECTION OUTPUT ;
    USE SIGNAL ;
    PORT
      LAYER met2 ;
        RECT 548.870 0.000 549.150 4.000 ;
    END
  END la_data_out[64]
  PIN la_data_out[65]
    DIRECTION OUTPUT ;
    USE SIGNAL ;
    PORT
      LAYER met2 ;
        RECT 552.090 0.000 552.370 4.000 ;
    END
  END la_data_out[65]
  PIN la_data_out[66]
    DIRECTION OUTPUT ;
    USE SIGNAL ;
    PORT
      LAYER met2 ;
        RECT 555.310 0.000 555.590 4.000 ;
    END
  END la_data_out[66]
  PIN la_data_out[67]
    DIRECTION OUTPUT ;
    USE SIGNAL ;
    PORT
      LAYER met2 ;
        RECT 558.530 0.000 558.810 4.000 ;
    END
  END la_data_out[67]
  PIN la_data_out[68]
    DIRECTION OUTPUT ;
    USE SIGNAL ;
    PORT
      LAYER met2 ;
        RECT 561.750 0.000 562.030 4.000 ;
    END
  END la_data_out[68]
  PIN la_data_out[69]
    DIRECTION OUTPUT ;
    USE SIGNAL ;
    PORT
      LAYER met2 ;
        RECT 564.970 0.000 565.250 4.000 ;
    END
  END la_data_out[69]
  PIN la_data_out[6]
    DIRECTION OUTPUT ;
    USE SIGNAL ;
    ANTENNADIFFAREA 2.673000 ;
    PORT
      LAYER met2 ;
        RECT 362.110 0.000 362.390 4.000 ;
    END
  END la_data_out[6]
  PIN la_data_out[70]
    DIRECTION OUTPUT ;
    USE SIGNAL ;
    PORT
      LAYER met2 ;
        RECT 568.190 0.000 568.470 4.000 ;
    END
  END la_data_out[70]
  PIN la_data_out[71]
    DIRECTION OUTPUT ;
    USE SIGNAL ;
    PORT
      LAYER met2 ;
        RECT 571.410 0.000 571.690 4.000 ;
    END
  END la_data_out[71]
  PIN la_data_out[72]
    DIRECTION OUTPUT ;
    USE SIGNAL ;
    PORT
      LAYER met2 ;
        RECT 574.630 0.000 574.910 4.000 ;
    END
  END la_data_out[72]
  PIN la_data_out[73]
    DIRECTION OUTPUT ;
    USE SIGNAL ;
    PORT
      LAYER met2 ;
        RECT 577.850 0.000 578.130 4.000 ;
    END
  END la_data_out[73]
  PIN la_data_out[74]
    DIRECTION OUTPUT ;
    USE SIGNAL ;
    PORT
      LAYER met2 ;
        RECT 581.070 0.000 581.350 4.000 ;
    END
  END la_data_out[74]
  PIN la_data_out[75]
    DIRECTION OUTPUT ;
    USE SIGNAL ;
    PORT
      LAYER met2 ;
        RECT 584.290 0.000 584.570 4.000 ;
    END
  END la_data_out[75]
  PIN la_data_out[76]
    DIRECTION OUTPUT ;
    USE SIGNAL ;
    PORT
      LAYER met2 ;
        RECT 587.510 0.000 587.790 4.000 ;
    END
  END la_data_out[76]
  PIN la_data_out[77]
    DIRECTION OUTPUT ;
    USE SIGNAL ;
    PORT
      LAYER met2 ;
        RECT 590.730 0.000 591.010 4.000 ;
    END
  END la_data_out[77]
  PIN la_data_out[78]
    DIRECTION OUTPUT ;
    USE SIGNAL ;
    PORT
      LAYER met2 ;
        RECT 593.950 0.000 594.230 4.000 ;
    END
  END la_data_out[78]
  PIN la_data_out[79]
    DIRECTION OUTPUT ;
    USE SIGNAL ;
    PORT
      LAYER met2 ;
        RECT 597.170 0.000 597.450 4.000 ;
    END
  END la_data_out[79]
  PIN la_data_out[7]
    DIRECTION OUTPUT ;
    USE SIGNAL ;
    ANTENNADIFFAREA 2.673000 ;
    PORT
      LAYER met2 ;
        RECT 365.330 0.000 365.610 4.000 ;
    END
  END la_data_out[7]
  PIN la_data_out[80]
    DIRECTION OUTPUT ;
    USE SIGNAL ;
    PORT
      LAYER met2 ;
        RECT 600.390 0.000 600.670 4.000 ;
    END
  END la_data_out[80]
  PIN la_data_out[81]
    DIRECTION OUTPUT ;
    USE SIGNAL ;
    PORT
      LAYER met2 ;
        RECT 603.610 0.000 603.890 4.000 ;
    END
  END la_data_out[81]
  PIN la_data_out[82]
    DIRECTION OUTPUT ;
    USE SIGNAL ;
    PORT
      LAYER met2 ;
        RECT 606.830 0.000 607.110 4.000 ;
    END
  END la_data_out[82]
  PIN la_data_out[83]
    DIRECTION OUTPUT ;
    USE SIGNAL ;
    PORT
      LAYER met2 ;
        RECT 610.050 0.000 610.330 4.000 ;
    END
  END la_data_out[83]
  PIN la_data_out[84]
    DIRECTION OUTPUT ;
    USE SIGNAL ;
    PORT
      LAYER met2 ;
        RECT 613.270 0.000 613.550 4.000 ;
    END
  END la_data_out[84]
  PIN la_data_out[85]
    DIRECTION OUTPUT ;
    USE SIGNAL ;
    PORT
      LAYER met2 ;
        RECT 616.490 0.000 616.770 4.000 ;
    END
  END la_data_out[85]
  PIN la_data_out[86]
    DIRECTION OUTPUT ;
    USE SIGNAL ;
    PORT
      LAYER met2 ;
        RECT 619.710 0.000 619.990 4.000 ;
    END
  END la_data_out[86]
  PIN la_data_out[87]
    DIRECTION OUTPUT ;
    USE SIGNAL ;
    PORT
      LAYER met2 ;
        RECT 622.930 0.000 623.210 4.000 ;
    END
  END la_data_out[87]
  PIN la_data_out[88]
    DIRECTION OUTPUT ;
    USE SIGNAL ;
    PORT
      LAYER met2 ;
        RECT 626.150 0.000 626.430 4.000 ;
    END
  END la_data_out[88]
  PIN la_data_out[89]
    DIRECTION OUTPUT ;
    USE SIGNAL ;
    PORT
      LAYER met2 ;
        RECT 629.370 0.000 629.650 4.000 ;
    END
  END la_data_out[89]
  PIN la_data_out[8]
    DIRECTION OUTPUT ;
    USE SIGNAL ;
    ANTENNADIFFAREA 2.673000 ;
    PORT
      LAYER met2 ;
        RECT 368.550 0.000 368.830 4.000 ;
    END
  END la_data_out[8]
  PIN la_data_out[90]
    DIRECTION OUTPUT ;
    USE SIGNAL ;
    PORT
      LAYER met2 ;
        RECT 632.590 0.000 632.870 4.000 ;
    END
  END la_data_out[90]
  PIN la_data_out[91]
    DIRECTION OUTPUT ;
    USE SIGNAL ;
    PORT
      LAYER met2 ;
        RECT 635.810 0.000 636.090 4.000 ;
    END
  END la_data_out[91]
  PIN la_data_out[92]
    DIRECTION OUTPUT ;
    USE SIGNAL ;
    PORT
      LAYER met2 ;
        RECT 639.030 0.000 639.310 4.000 ;
    END
  END la_data_out[92]
  PIN la_data_out[93]
    DIRECTION OUTPUT ;
    USE SIGNAL ;
    PORT
      LAYER met2 ;
        RECT 642.250 0.000 642.530 4.000 ;
    END
  END la_data_out[93]
  PIN la_data_out[94]
    DIRECTION OUTPUT ;
    USE SIGNAL ;
    PORT
      LAYER met2 ;
        RECT 645.470 0.000 645.750 4.000 ;
    END
  END la_data_out[94]
  PIN la_data_out[95]
    DIRECTION OUTPUT ;
    USE SIGNAL ;
    PORT
      LAYER met2 ;
        RECT 648.690 0.000 648.970 4.000 ;
    END
  END la_data_out[95]
  PIN la_data_out[96]
    DIRECTION OUTPUT ;
    USE SIGNAL ;
    PORT
      LAYER met2 ;
        RECT 651.910 0.000 652.190 4.000 ;
    END
  END la_data_out[96]
  PIN la_data_out[97]
    DIRECTION OUTPUT ;
    USE SIGNAL ;
    PORT
      LAYER met2 ;
        RECT 655.130 0.000 655.410 4.000 ;
    END
  END la_data_out[97]
  PIN la_data_out[98]
    DIRECTION OUTPUT ;
    USE SIGNAL ;
    PORT
      LAYER met2 ;
        RECT 658.350 0.000 658.630 4.000 ;
    END
  END la_data_out[98]
  PIN la_data_out[99]
    DIRECTION OUTPUT ;
    USE SIGNAL ;
    PORT
      LAYER met2 ;
        RECT 661.570 0.000 661.850 4.000 ;
    END
  END la_data_out[99]
  PIN la_data_out[9]
    DIRECTION OUTPUT ;
    USE SIGNAL ;
    ANTENNADIFFAREA 2.673000 ;
    PORT
      LAYER met2 ;
        RECT 371.770 0.000 372.050 4.000 ;
    END
  END la_data_out[9]
  PIN vccd1
    DIRECTION INOUT ;
    USE POWER ;
    PORT
      LAYER met4 ;
        RECT 21.040 10.640 22.640 761.840 ;
    END
    PORT
      LAYER met4 ;
        RECT 174.640 10.640 176.240 761.840 ;
    END
    PORT
      LAYER met4 ;
        RECT 328.240 10.640 329.840 761.840 ;
    END
    PORT
      LAYER met4 ;
        RECT 481.840 10.640 483.440 761.840 ;
    END
    PORT
      LAYER met4 ;
        RECT 635.440 10.640 637.040 761.840 ;
    END
  END vccd1
  PIN vssd1
    DIRECTION INOUT ;
    USE GROUND ;
    PORT
      LAYER met4 ;
        RECT 97.840 10.640 99.440 761.840 ;
    END
    PORT
      LAYER met4 ;
        RECT 251.440 10.640 253.040 761.840 ;
    END
    PORT
      LAYER met4 ;
        RECT 405.040 10.640 406.640 761.840 ;
    END
    PORT
      LAYER met4 ;
        RECT 558.640 10.640 560.240 761.840 ;
    END
    PORT
      LAYER met4 ;
        RECT 712.240 10.640 713.840 761.840 ;
    END
  END vssd1
  PIN wb_clk_i
    DIRECTION INPUT ;
    USE SIGNAL ;
    ANTENNAGATEAREA 1.286700 ;
    ANTENNADIFFAREA 0.434700 ;
    PORT
      LAYER met2 ;
        RECT 1.470 0.000 1.750 4.000 ;
    END
  END wb_clk_i
  PIN wb_rst_i
    DIRECTION INPUT ;
    USE SIGNAL ;
    ANTENNAGATEAREA 0.247500 ;
    PORT
      LAYER met2 ;
        RECT 4.690 0.000 4.970 4.000 ;
    END
  END wb_rst_i
  PIN wbs_ack_o
    DIRECTION OUTPUT ;
    USE SIGNAL ;
    ANTENNADIFFAREA 2.673000 ;
    PORT
      LAYER met2 ;
        RECT 7.910 0.000 8.190 4.000 ;
    END
  END wbs_ack_o
  PIN wbs_adr_i[0]
    DIRECTION INPUT ;
    USE SIGNAL ;
    PORT
      LAYER met2 ;
        RECT 20.790 0.000 21.070 4.000 ;
    END
  END wbs_adr_i[0]
  PIN wbs_adr_i[10]
    DIRECTION INPUT ;
    USE SIGNAL ;
    PORT
      LAYER met2 ;
        RECT 130.270 0.000 130.550 4.000 ;
    END
  END wbs_adr_i[10]
  PIN wbs_adr_i[11]
    DIRECTION INPUT ;
    USE SIGNAL ;
    PORT
      LAYER met2 ;
        RECT 139.930 0.000 140.210 4.000 ;
    END
  END wbs_adr_i[11]
  PIN wbs_adr_i[12]
    DIRECTION INPUT ;
    USE SIGNAL ;
    ANTENNAGATEAREA 0.126000 ;
    PORT
      LAYER met2 ;
        RECT 149.590 0.000 149.870 4.000 ;
    END
  END wbs_adr_i[12]
  PIN wbs_adr_i[13]
    DIRECTION INPUT ;
    USE SIGNAL ;
    PORT
      LAYER met2 ;
        RECT 159.250 0.000 159.530 4.000 ;
    END
  END wbs_adr_i[13]
  PIN wbs_adr_i[14]
    DIRECTION INPUT ;
    USE SIGNAL ;
    PORT
      LAYER met2 ;
        RECT 168.910 0.000 169.190 4.000 ;
    END
  END wbs_adr_i[14]
  PIN wbs_adr_i[15]
    DIRECTION INPUT ;
    USE SIGNAL ;
    PORT
      LAYER met2 ;
        RECT 178.570 0.000 178.850 4.000 ;
    END
  END wbs_adr_i[15]
  PIN wbs_adr_i[16]
    DIRECTION INPUT ;
    USE SIGNAL ;
    PORT
      LAYER met2 ;
        RECT 188.230 0.000 188.510 4.000 ;
    END
  END wbs_adr_i[16]
  PIN wbs_adr_i[17]
    DIRECTION INPUT ;
    USE SIGNAL ;
    PORT
      LAYER met2 ;
        RECT 197.890 0.000 198.170 4.000 ;
    END
  END wbs_adr_i[17]
  PIN wbs_adr_i[18]
    DIRECTION INPUT ;
    USE SIGNAL ;
    PORT
      LAYER met2 ;
        RECT 207.550 0.000 207.830 4.000 ;
    END
  END wbs_adr_i[18]
  PIN wbs_adr_i[19]
    DIRECTION INPUT ;
    USE SIGNAL ;
    PORT
      LAYER met2 ;
        RECT 217.210 0.000 217.490 4.000 ;
    END
  END wbs_adr_i[19]
  PIN wbs_adr_i[1]
    DIRECTION INPUT ;
    USE SIGNAL ;
    PORT
      LAYER met2 ;
        RECT 33.670 0.000 33.950 4.000 ;
    END
  END wbs_adr_i[1]
  PIN wbs_adr_i[20]
    DIRECTION INPUT ;
    USE SIGNAL ;
    PORT
      LAYER met2 ;
        RECT 226.870 0.000 227.150 4.000 ;
    END
  END wbs_adr_i[20]
  PIN wbs_adr_i[21]
    DIRECTION INPUT ;
    USE SIGNAL ;
    PORT
      LAYER met2 ;
        RECT 236.530 0.000 236.810 4.000 ;
    END
  END wbs_adr_i[21]
  PIN wbs_adr_i[22]
    DIRECTION INPUT ;
    USE SIGNAL ;
    PORT
      LAYER met2 ;
        RECT 246.190 0.000 246.470 4.000 ;
    END
  END wbs_adr_i[22]
  PIN wbs_adr_i[23]
    DIRECTION INPUT ;
    USE SIGNAL ;
    PORT
      LAYER met2 ;
        RECT 255.850 0.000 256.130 4.000 ;
    END
  END wbs_adr_i[23]
  PIN wbs_adr_i[24]
    DIRECTION INPUT ;
    USE SIGNAL ;
    PORT
      LAYER met2 ;
        RECT 265.510 0.000 265.790 4.000 ;
    END
  END wbs_adr_i[24]
  PIN wbs_adr_i[25]
    DIRECTION INPUT ;
    USE SIGNAL ;
    PORT
      LAYER met2 ;
        RECT 275.170 0.000 275.450 4.000 ;
    END
  END wbs_adr_i[25]
  PIN wbs_adr_i[26]
    DIRECTION INPUT ;
    USE SIGNAL ;
    PORT
      LAYER met2 ;
        RECT 284.830 0.000 285.110 4.000 ;
    END
  END wbs_adr_i[26]
  PIN wbs_adr_i[27]
    DIRECTION INPUT ;
    USE SIGNAL ;
    PORT
      LAYER met2 ;
        RECT 294.490 0.000 294.770 4.000 ;
    END
  END wbs_adr_i[27]
  PIN wbs_adr_i[28]
    DIRECTION INPUT ;
    USE SIGNAL ;
    PORT
      LAYER met2 ;
        RECT 304.150 0.000 304.430 4.000 ;
    END
  END wbs_adr_i[28]
  PIN wbs_adr_i[29]
    DIRECTION INPUT ;
    USE SIGNAL ;
    PORT
      LAYER met2 ;
        RECT 313.810 0.000 314.090 4.000 ;
    END
  END wbs_adr_i[29]
  PIN wbs_adr_i[2]
    DIRECTION INPUT ;
    USE SIGNAL ;
    ANTENNAGATEAREA 0.126000 ;
    PORT
      LAYER met2 ;
        RECT 46.550 0.000 46.830 4.000 ;
    END
  END wbs_adr_i[2]
  PIN wbs_adr_i[30]
    DIRECTION INPUT ;
    USE SIGNAL ;
    PORT
      LAYER met2 ;
        RECT 323.470 0.000 323.750 4.000 ;
    END
  END wbs_adr_i[30]
  PIN wbs_adr_i[31]
    DIRECTION INPUT ;
    USE SIGNAL ;
    PORT
      LAYER met2 ;
        RECT 333.130 0.000 333.410 4.000 ;
    END
  END wbs_adr_i[31]
  PIN wbs_adr_i[3]
    DIRECTION INPUT ;
    USE SIGNAL ;
    ANTENNAGATEAREA 0.126000 ;
    PORT
      LAYER met2 ;
        RECT 59.430 0.000 59.710 4.000 ;
    END
  END wbs_adr_i[3]
  PIN wbs_adr_i[4]
    DIRECTION INPUT ;
    USE SIGNAL ;
    ANTENNAGATEAREA 0.126000 ;
    PORT
      LAYER met2 ;
        RECT 72.310 0.000 72.590 4.000 ;
    END
  END wbs_adr_i[4]
  PIN wbs_adr_i[5]
    DIRECTION INPUT ;
    USE SIGNAL ;
    ANTENNAGATEAREA 0.126000 ;
    PORT
      LAYER met2 ;
        RECT 81.970 0.000 82.250 4.000 ;
    END
  END wbs_adr_i[5]
  PIN wbs_adr_i[6]
    DIRECTION INPUT ;
    USE SIGNAL ;
    ANTENNAGATEAREA 0.126000 ;
    PORT
      LAYER met2 ;
        RECT 91.630 0.000 91.910 4.000 ;
    END
  END wbs_adr_i[6]
  PIN wbs_adr_i[7]
    DIRECTION INPUT ;
    USE SIGNAL ;
    ANTENNAGATEAREA 0.126000 ;
    PORT
      LAYER met2 ;
        RECT 101.290 0.000 101.570 4.000 ;
    END
  END wbs_adr_i[7]
  PIN wbs_adr_i[8]
    DIRECTION INPUT ;
    USE SIGNAL ;
    ANTENNAGATEAREA 0.126000 ;
    PORT
      LAYER met2 ;
        RECT 110.950 0.000 111.230 4.000 ;
    END
  END wbs_adr_i[8]
  PIN wbs_adr_i[9]
    DIRECTION INPUT ;
    USE SIGNAL ;
    PORT
      LAYER met2 ;
        RECT 120.610 0.000 120.890 4.000 ;
    END
  END wbs_adr_i[9]
  PIN wbs_cyc_i
    DIRECTION INPUT ;
    USE SIGNAL ;
    ANTENNAGATEAREA 0.159000 ;
    PORT
      LAYER met2 ;
        RECT 11.130 0.000 11.410 4.000 ;
    END
  END wbs_cyc_i
  PIN wbs_dat_i[0]
    DIRECTION INPUT ;
    USE SIGNAL ;
    ANTENNAGATEAREA 0.126000 ;
    PORT
      LAYER met2 ;
        RECT 24.010 0.000 24.290 4.000 ;
    END
  END wbs_dat_i[0]
  PIN wbs_dat_i[10]
    DIRECTION INPUT ;
    USE SIGNAL ;
    ANTENNAGATEAREA 0.126000 ;
    PORT
      LAYER met2 ;
        RECT 133.490 0.000 133.770 4.000 ;
    END
  END wbs_dat_i[10]
  PIN wbs_dat_i[11]
    DIRECTION INPUT ;
    USE SIGNAL ;
    ANTENNAGATEAREA 0.126000 ;
    PORT
      LAYER met2 ;
        RECT 143.150 0.000 143.430 4.000 ;
    END
  END wbs_dat_i[11]
  PIN wbs_dat_i[12]
    DIRECTION INPUT ;
    USE SIGNAL ;
    ANTENNAGATEAREA 0.126000 ;
    PORT
      LAYER met2 ;
        RECT 152.810 0.000 153.090 4.000 ;
    END
  END wbs_dat_i[12]
  PIN wbs_dat_i[13]
    DIRECTION INPUT ;
    USE SIGNAL ;
    ANTENNAGATEAREA 0.126000 ;
    PORT
      LAYER met2 ;
        RECT 162.470 0.000 162.750 4.000 ;
    END
  END wbs_dat_i[13]
  PIN wbs_dat_i[14]
    DIRECTION INPUT ;
    USE SIGNAL ;
    ANTENNAGATEAREA 0.126000 ;
    PORT
      LAYER met2 ;
        RECT 172.130 0.000 172.410 4.000 ;
    END
  END wbs_dat_i[14]
  PIN wbs_dat_i[15]
    DIRECTION INPUT ;
    USE SIGNAL ;
    ANTENNAGATEAREA 0.126000 ;
    PORT
      LAYER met2 ;
        RECT 181.790 0.000 182.070 4.000 ;
    END
  END wbs_dat_i[15]
  PIN wbs_dat_i[16]
    DIRECTION INPUT ;
    USE SIGNAL ;
    ANTENNAGATEAREA 0.126000 ;
    PORT
      LAYER met2 ;
        RECT 191.450 0.000 191.730 4.000 ;
    END
  END wbs_dat_i[16]
  PIN wbs_dat_i[17]
    DIRECTION INPUT ;
    USE SIGNAL ;
    ANTENNAGATEAREA 0.126000 ;
    PORT
      LAYER met2 ;
        RECT 201.110 0.000 201.390 4.000 ;
    END
  END wbs_dat_i[17]
  PIN wbs_dat_i[18]
    DIRECTION INPUT ;
    USE SIGNAL ;
    ANTENNAGATEAREA 0.126000 ;
    PORT
      LAYER met2 ;
        RECT 210.770 0.000 211.050 4.000 ;
    END
  END wbs_dat_i[18]
  PIN wbs_dat_i[19]
    DIRECTION INPUT ;
    USE SIGNAL ;
    ANTENNAGATEAREA 0.126000 ;
    PORT
      LAYER met2 ;
        RECT 220.430 0.000 220.710 4.000 ;
    END
  END wbs_dat_i[19]
  PIN wbs_dat_i[1]
    DIRECTION INPUT ;
    USE SIGNAL ;
    ANTENNAGATEAREA 0.126000 ;
    PORT
      LAYER met2 ;
        RECT 36.890 0.000 37.170 4.000 ;
    END
  END wbs_dat_i[1]
  PIN wbs_dat_i[20]
    DIRECTION INPUT ;
    USE SIGNAL ;
    ANTENNAGATEAREA 0.126000 ;
    PORT
      LAYER met2 ;
        RECT 230.090 0.000 230.370 4.000 ;
    END
  END wbs_dat_i[20]
  PIN wbs_dat_i[21]
    DIRECTION INPUT ;
    USE SIGNAL ;
    ANTENNAGATEAREA 0.126000 ;
    PORT
      LAYER met2 ;
        RECT 239.750 0.000 240.030 4.000 ;
    END
  END wbs_dat_i[21]
  PIN wbs_dat_i[22]
    DIRECTION INPUT ;
    USE SIGNAL ;
    ANTENNAGATEAREA 0.126000 ;
    PORT
      LAYER met2 ;
        RECT 249.410 0.000 249.690 4.000 ;
    END
  END wbs_dat_i[22]
  PIN wbs_dat_i[23]
    DIRECTION INPUT ;
    USE SIGNAL ;
    ANTENNAGATEAREA 0.126000 ;
    PORT
      LAYER met2 ;
        RECT 259.070 0.000 259.350 4.000 ;
    END
  END wbs_dat_i[23]
  PIN wbs_dat_i[24]
    DIRECTION INPUT ;
    USE SIGNAL ;
    ANTENNAGATEAREA 0.126000 ;
    PORT
      LAYER met2 ;
        RECT 268.730 0.000 269.010 4.000 ;
    END
  END wbs_dat_i[24]
  PIN wbs_dat_i[25]
    DIRECTION INPUT ;
    USE SIGNAL ;
    ANTENNAGATEAREA 0.126000 ;
    PORT
      LAYER met2 ;
        RECT 278.390 0.000 278.670 4.000 ;
    END
  END wbs_dat_i[25]
  PIN wbs_dat_i[26]
    DIRECTION INPUT ;
    USE SIGNAL ;
    ANTENNAGATEAREA 0.126000 ;
    PORT
      LAYER met2 ;
        RECT 288.050 0.000 288.330 4.000 ;
    END
  END wbs_dat_i[26]
  PIN wbs_dat_i[27]
    DIRECTION INPUT ;
    USE SIGNAL ;
    ANTENNAGATEAREA 0.126000 ;
    PORT
      LAYER met2 ;
        RECT 297.710 0.000 297.990 4.000 ;
    END
  END wbs_dat_i[27]
  PIN wbs_dat_i[28]
    DIRECTION INPUT ;
    USE SIGNAL ;
    ANTENNAGATEAREA 0.126000 ;
    PORT
      LAYER met2 ;
        RECT 307.370 0.000 307.650 4.000 ;
    END
  END wbs_dat_i[28]
  PIN wbs_dat_i[29]
    DIRECTION INPUT ;
    USE SIGNAL ;
    ANTENNAGATEAREA 0.126000 ;
    PORT
      LAYER met2 ;
        RECT 317.030 0.000 317.310 4.000 ;
    END
  END wbs_dat_i[29]
  PIN wbs_dat_i[2]
    DIRECTION INPUT ;
    USE SIGNAL ;
    ANTENNAGATEAREA 0.126000 ;
    PORT
      LAYER met2 ;
        RECT 49.770 0.000 50.050 4.000 ;
    END
  END wbs_dat_i[2]
  PIN wbs_dat_i[30]
    DIRECTION INPUT ;
    USE SIGNAL ;
    ANTENNAGATEAREA 0.126000 ;
    PORT
      LAYER met2 ;
        RECT 326.690 0.000 326.970 4.000 ;
    END
  END wbs_dat_i[30]
  PIN wbs_dat_i[31]
    DIRECTION INPUT ;
    USE SIGNAL ;
    ANTENNAGATEAREA 0.126000 ;
    PORT
      LAYER met2 ;
        RECT 336.350 0.000 336.630 4.000 ;
    END
  END wbs_dat_i[31]
  PIN wbs_dat_i[3]
    DIRECTION INPUT ;
    USE SIGNAL ;
    ANTENNAGATEAREA 0.126000 ;
    PORT
      LAYER met2 ;
        RECT 62.650 0.000 62.930 4.000 ;
    END
  END wbs_dat_i[3]
  PIN wbs_dat_i[4]
    DIRECTION INPUT ;
    USE SIGNAL ;
    ANTENNAGATEAREA 0.126000 ;
    PORT
      LAYER met2 ;
        RECT 75.530 0.000 75.810 4.000 ;
    END
  END wbs_dat_i[4]
  PIN wbs_dat_i[5]
    DIRECTION INPUT ;
    USE SIGNAL ;
    ANTENNAGATEAREA 0.126000 ;
    PORT
      LAYER met2 ;
        RECT 85.190 0.000 85.470 4.000 ;
    END
  END wbs_dat_i[5]
  PIN wbs_dat_i[6]
    DIRECTION INPUT ;
    USE SIGNAL ;
    ANTENNAGATEAREA 0.126000 ;
    PORT
      LAYER met2 ;
        RECT 94.850 0.000 95.130 4.000 ;
    END
  END wbs_dat_i[6]
  PIN wbs_dat_i[7]
    DIRECTION INPUT ;
    USE SIGNAL ;
    ANTENNAGATEAREA 0.126000 ;
    PORT
      LAYER met2 ;
        RECT 104.510 0.000 104.790 4.000 ;
    END
  END wbs_dat_i[7]
  PIN wbs_dat_i[8]
    DIRECTION INPUT ;
    USE SIGNAL ;
    ANTENNAGATEAREA 0.126000 ;
    PORT
      LAYER met2 ;
        RECT 114.170 0.000 114.450 4.000 ;
    END
  END wbs_dat_i[8]
  PIN wbs_dat_i[9]
    DIRECTION INPUT ;
    USE SIGNAL ;
    ANTENNAGATEAREA 0.126000 ;
    PORT
      LAYER met2 ;
        RECT 123.830 0.000 124.110 4.000 ;
    END
  END wbs_dat_i[9]
  PIN wbs_dat_o[0]
    DIRECTION OUTPUT ;
    USE SIGNAL ;
    ANTENNADIFFAREA 2.673000 ;
    PORT
      LAYER met2 ;
        RECT 27.230 0.000 27.510 4.000 ;
    END
  END wbs_dat_o[0]
  PIN wbs_dat_o[10]
    DIRECTION OUTPUT ;
    USE SIGNAL ;
    ANTENNADIFFAREA 2.673000 ;
    PORT
      LAYER met2 ;
        RECT 136.710 0.000 136.990 4.000 ;
    END
  END wbs_dat_o[10]
  PIN wbs_dat_o[11]
    DIRECTION OUTPUT ;
    USE SIGNAL ;
    ANTENNADIFFAREA 2.673000 ;
    PORT
      LAYER met2 ;
        RECT 146.370 0.000 146.650 4.000 ;
    END
  END wbs_dat_o[11]
  PIN wbs_dat_o[12]
    DIRECTION OUTPUT ;
    USE SIGNAL ;
    ANTENNADIFFAREA 2.673000 ;
    PORT
      LAYER met2 ;
        RECT 156.030 0.000 156.310 4.000 ;
    END
  END wbs_dat_o[12]
  PIN wbs_dat_o[13]
    DIRECTION OUTPUT ;
    USE SIGNAL ;
    ANTENNADIFFAREA 2.673000 ;
    PORT
      LAYER met2 ;
        RECT 165.690 0.000 165.970 4.000 ;
    END
  END wbs_dat_o[13]
  PIN wbs_dat_o[14]
    DIRECTION OUTPUT ;
    USE SIGNAL ;
    ANTENNADIFFAREA 2.673000 ;
    PORT
      LAYER met2 ;
        RECT 175.350 0.000 175.630 4.000 ;
    END
  END wbs_dat_o[14]
  PIN wbs_dat_o[15]
    DIRECTION OUTPUT ;
    USE SIGNAL ;
    ANTENNADIFFAREA 2.673000 ;
    PORT
      LAYER met2 ;
        RECT 185.010 0.000 185.290 4.000 ;
    END
  END wbs_dat_o[15]
  PIN wbs_dat_o[16]
    DIRECTION OUTPUT ;
    USE SIGNAL ;
    ANTENNADIFFAREA 2.673000 ;
    PORT
      LAYER met2 ;
        RECT 194.670 0.000 194.950 4.000 ;
    END
  END wbs_dat_o[16]
  PIN wbs_dat_o[17]
    DIRECTION OUTPUT ;
    USE SIGNAL ;
    ANTENNADIFFAREA 2.673000 ;
    PORT
      LAYER met2 ;
        RECT 204.330 0.000 204.610 4.000 ;
    END
  END wbs_dat_o[17]
  PIN wbs_dat_o[18]
    DIRECTION OUTPUT ;
    USE SIGNAL ;
    ANTENNADIFFAREA 2.673000 ;
    PORT
      LAYER met2 ;
        RECT 213.990 0.000 214.270 4.000 ;
    END
  END wbs_dat_o[18]
  PIN wbs_dat_o[19]
    DIRECTION OUTPUT ;
    USE SIGNAL ;
    ANTENNADIFFAREA 2.673000 ;
    PORT
      LAYER met2 ;
        RECT 223.650 0.000 223.930 4.000 ;
    END
  END wbs_dat_o[19]
  PIN wbs_dat_o[1]
    DIRECTION OUTPUT ;
    USE SIGNAL ;
    ANTENNADIFFAREA 2.673000 ;
    PORT
      LAYER met2 ;
        RECT 40.110 0.000 40.390 4.000 ;
    END
  END wbs_dat_o[1]
  PIN wbs_dat_o[20]
    DIRECTION OUTPUT ;
    USE SIGNAL ;
    ANTENNADIFFAREA 2.673000 ;
    PORT
      LAYER met2 ;
        RECT 233.310 0.000 233.590 4.000 ;
    END
  END wbs_dat_o[20]
  PIN wbs_dat_o[21]
    DIRECTION OUTPUT ;
    USE SIGNAL ;
    ANTENNADIFFAREA 2.673000 ;
    PORT
      LAYER met2 ;
        RECT 242.970 0.000 243.250 4.000 ;
    END
  END wbs_dat_o[21]
  PIN wbs_dat_o[22]
    DIRECTION OUTPUT ;
    USE SIGNAL ;
    ANTENNADIFFAREA 2.673000 ;
    PORT
      LAYER met2 ;
        RECT 252.630 0.000 252.910 4.000 ;
    END
  END wbs_dat_o[22]
  PIN wbs_dat_o[23]
    DIRECTION OUTPUT ;
    USE SIGNAL ;
    ANTENNADIFFAREA 2.673000 ;
    PORT
      LAYER met2 ;
        RECT 262.290 0.000 262.570 4.000 ;
    END
  END wbs_dat_o[23]
  PIN wbs_dat_o[24]
    DIRECTION OUTPUT ;
    USE SIGNAL ;
    ANTENNADIFFAREA 2.673000 ;
    PORT
      LAYER met2 ;
        RECT 271.950 0.000 272.230 4.000 ;
    END
  END wbs_dat_o[24]
  PIN wbs_dat_o[25]
    DIRECTION OUTPUT ;
    USE SIGNAL ;
    ANTENNADIFFAREA 2.673000 ;
    PORT
      LAYER met2 ;
        RECT 281.610 0.000 281.890 4.000 ;
    END
  END wbs_dat_o[25]
  PIN wbs_dat_o[26]
    DIRECTION OUTPUT ;
    USE SIGNAL ;
    ANTENNADIFFAREA 2.673000 ;
    PORT
      LAYER met2 ;
        RECT 291.270 0.000 291.550 4.000 ;
    END
  END wbs_dat_o[26]
  PIN wbs_dat_o[27]
    DIRECTION OUTPUT ;
    USE SIGNAL ;
    ANTENNADIFFAREA 2.673000 ;
    PORT
      LAYER met2 ;
        RECT 300.930 0.000 301.210 4.000 ;
    END
  END wbs_dat_o[27]
  PIN wbs_dat_o[28]
    DIRECTION OUTPUT ;
    USE SIGNAL ;
    ANTENNADIFFAREA 2.673000 ;
    PORT
      LAYER met2 ;
        RECT 310.590 0.000 310.870 4.000 ;
    END
  END wbs_dat_o[28]
  PIN wbs_dat_o[29]
    DIRECTION OUTPUT ;
    USE SIGNAL ;
    ANTENNADIFFAREA 2.673000 ;
    PORT
      LAYER met2 ;
        RECT 320.250 0.000 320.530 4.000 ;
    END
  END wbs_dat_o[29]
  PIN wbs_dat_o[2]
    DIRECTION OUTPUT ;
    USE SIGNAL ;
    ANTENNADIFFAREA 2.673000 ;
    PORT
      LAYER met2 ;
        RECT 52.990 0.000 53.270 4.000 ;
    END
  END wbs_dat_o[2]
  PIN wbs_dat_o[30]
    DIRECTION OUTPUT ;
    USE SIGNAL ;
    ANTENNADIFFAREA 2.673000 ;
    PORT
      LAYER met2 ;
        RECT 329.910 0.000 330.190 4.000 ;
    END
  END wbs_dat_o[30]
  PIN wbs_dat_o[31]
    DIRECTION OUTPUT ;
    USE SIGNAL ;
    ANTENNADIFFAREA 2.673000 ;
    PORT
      LAYER met2 ;
        RECT 339.570 0.000 339.850 4.000 ;
    END
  END wbs_dat_o[31]
  PIN wbs_dat_o[3]
    DIRECTION OUTPUT ;
    USE SIGNAL ;
    ANTENNADIFFAREA 2.673000 ;
    PORT
      LAYER met2 ;
        RECT 65.870 0.000 66.150 4.000 ;
    END
  END wbs_dat_o[3]
  PIN wbs_dat_o[4]
    DIRECTION OUTPUT ;
    USE SIGNAL ;
    ANTENNADIFFAREA 2.673000 ;
    PORT
      LAYER met2 ;
        RECT 78.750 0.000 79.030 4.000 ;
    END
  END wbs_dat_o[4]
  PIN wbs_dat_o[5]
    DIRECTION OUTPUT ;
    USE SIGNAL ;
    ANTENNADIFFAREA 2.673000 ;
    PORT
      LAYER met2 ;
        RECT 88.410 0.000 88.690 4.000 ;
    END
  END wbs_dat_o[5]
  PIN wbs_dat_o[6]
    DIRECTION OUTPUT ;
    USE SIGNAL ;
    ANTENNADIFFAREA 2.673000 ;
    PORT
      LAYER met2 ;
        RECT 98.070 0.000 98.350 4.000 ;
    END
  END wbs_dat_o[6]
  PIN wbs_dat_o[7]
    DIRECTION OUTPUT ;
    USE SIGNAL ;
    ANTENNADIFFAREA 2.673000 ;
    PORT
      LAYER met2 ;
        RECT 107.730 0.000 108.010 4.000 ;
    END
  END wbs_dat_o[7]
  PIN wbs_dat_o[8]
    DIRECTION OUTPUT ;
    USE SIGNAL ;
    ANTENNADIFFAREA 2.673000 ;
    PORT
      LAYER met2 ;
        RECT 117.390 0.000 117.670 4.000 ;
    END
  END wbs_dat_o[8]
  PIN wbs_dat_o[9]
    DIRECTION OUTPUT ;
    USE SIGNAL ;
    ANTENNADIFFAREA 2.673000 ;
    PORT
      LAYER met2 ;
        RECT 127.050 0.000 127.330 4.000 ;
    END
  END wbs_dat_o[9]
  PIN wbs_sel_i[0]
    DIRECTION INPUT ;
    USE SIGNAL ;
    ANTENNAGATEAREA 0.126000 ;
    PORT
      LAYER met2 ;
        RECT 30.450 0.000 30.730 4.000 ;
    END
  END wbs_sel_i[0]
  PIN wbs_sel_i[1]
    DIRECTION INPUT ;
    USE SIGNAL ;
    ANTENNAGATEAREA 0.126000 ;
    PORT
      LAYER met2 ;
        RECT 43.330 0.000 43.610 4.000 ;
    END
  END wbs_sel_i[1]
  PIN wbs_sel_i[2]
    DIRECTION INPUT ;
    USE SIGNAL ;
    ANTENNAGATEAREA 0.126000 ;
    PORT
      LAYER met2 ;
        RECT 56.210 0.000 56.490 4.000 ;
    END
  END wbs_sel_i[2]
  PIN wbs_sel_i[3]
    DIRECTION INPUT ;
    USE SIGNAL ;
    ANTENNAGATEAREA 0.126000 ;
    PORT
      LAYER met2 ;
        RECT 69.090 0.000 69.370 4.000 ;
    END
  END wbs_sel_i[3]
  PIN wbs_stb_i
    DIRECTION INPUT ;
    USE SIGNAL ;
    ANTENNAGATEAREA 0.159000 ;
    PORT
      LAYER met2 ;
        RECT 14.350 0.000 14.630 4.000 ;
    END
  END wbs_stb_i
  PIN wbs_we_i
    DIRECTION INPUT ;
    USE SIGNAL ;
    ANTENNAGATEAREA 0.126000 ;
    PORT
      LAYER met2 ;
        RECT 17.570 0.000 17.850 4.000 ;
    END
  END wbs_we_i
  OBS
      LAYER nwell ;
        RECT 5.330 10.795 758.270 761.685 ;
      LAYER li1 ;
        RECT 5.520 10.795 758.080 761.685 ;
      LAYER met1 ;
        RECT 4.210 1.060 761.690 761.840 ;
      LAYER met2 ;
        RECT 1.540 770.255 16.370 770.535 ;
        RECT 17.210 770.255 44.430 770.535 ;
        RECT 45.270 770.255 72.490 770.535 ;
        RECT 73.330 770.255 100.550 770.535 ;
        RECT 101.390 770.255 128.610 770.535 ;
        RECT 129.450 770.255 156.670 770.535 ;
        RECT 157.510 770.255 184.730 770.535 ;
        RECT 185.570 770.255 212.790 770.535 ;
        RECT 213.630 770.255 240.850 770.535 ;
        RECT 241.690 770.255 268.910 770.535 ;
        RECT 269.750 770.255 296.970 770.535 ;
        RECT 297.810 770.255 325.030 770.535 ;
        RECT 325.870 770.255 353.090 770.535 ;
        RECT 353.930 770.255 381.150 770.535 ;
        RECT 381.990 770.255 409.210 770.535 ;
        RECT 410.050 770.255 437.270 770.535 ;
        RECT 438.110 770.255 465.330 770.535 ;
        RECT 466.170 770.255 493.390 770.535 ;
        RECT 494.230 770.255 521.450 770.535 ;
        RECT 522.290 770.255 549.510 770.535 ;
        RECT 550.350 770.255 577.570 770.535 ;
        RECT 578.410 770.255 605.630 770.535 ;
        RECT 606.470 770.255 633.690 770.535 ;
        RECT 634.530 770.255 661.750 770.535 ;
        RECT 662.590 770.255 689.810 770.535 ;
        RECT 690.650 770.255 717.870 770.535 ;
        RECT 718.710 770.255 745.930 770.535 ;
        RECT 746.770 770.255 761.660 770.535 ;
        RECT 1.540 4.280 761.660 770.255 ;
        RECT 2.030 0.155 4.410 4.280 ;
        RECT 5.250 0.155 7.630 4.280 ;
        RECT 8.470 0.155 10.850 4.280 ;
        RECT 11.690 0.155 14.070 4.280 ;
        RECT 14.910 0.155 17.290 4.280 ;
        RECT 18.130 0.155 20.510 4.280 ;
        RECT 21.350 0.155 23.730 4.280 ;
        RECT 24.570 0.155 26.950 4.280 ;
        RECT 27.790 0.155 30.170 4.280 ;
        RECT 31.010 0.155 33.390 4.280 ;
        RECT 34.230 0.155 36.610 4.280 ;
        RECT 37.450 0.155 39.830 4.280 ;
        RECT 40.670 0.155 43.050 4.280 ;
        RECT 43.890 0.155 46.270 4.280 ;
        RECT 47.110 0.155 49.490 4.280 ;
        RECT 50.330 0.155 52.710 4.280 ;
        RECT 53.550 0.155 55.930 4.280 ;
        RECT 56.770 0.155 59.150 4.280 ;
        RECT 59.990 0.155 62.370 4.280 ;
        RECT 63.210 0.155 65.590 4.280 ;
        RECT 66.430 0.155 68.810 4.280 ;
        RECT 69.650 0.155 72.030 4.280 ;
        RECT 72.870 0.155 75.250 4.280 ;
        RECT 76.090 0.155 78.470 4.280 ;
        RECT 79.310 0.155 81.690 4.280 ;
        RECT 82.530 0.155 84.910 4.280 ;
        RECT 85.750 0.155 88.130 4.280 ;
        RECT 88.970 0.155 91.350 4.280 ;
        RECT 92.190 0.155 94.570 4.280 ;
        RECT 95.410 0.155 97.790 4.280 ;
        RECT 98.630 0.155 101.010 4.280 ;
        RECT 101.850 0.155 104.230 4.280 ;
        RECT 105.070 0.155 107.450 4.280 ;
        RECT 108.290 0.155 110.670 4.280 ;
        RECT 111.510 0.155 113.890 4.280 ;
        RECT 114.730 0.155 117.110 4.280 ;
        RECT 117.950 0.155 120.330 4.280 ;
        RECT 121.170 0.155 123.550 4.280 ;
        RECT 124.390 0.155 126.770 4.280 ;
        RECT 127.610 0.155 129.990 4.280 ;
        RECT 130.830 0.155 133.210 4.280 ;
        RECT 134.050 0.155 136.430 4.280 ;
        RECT 137.270 0.155 139.650 4.280 ;
        RECT 140.490 0.155 142.870 4.280 ;
        RECT 143.710 0.155 146.090 4.280 ;
        RECT 146.930 0.155 149.310 4.280 ;
        RECT 150.150 0.155 152.530 4.280 ;
        RECT 153.370 0.155 155.750 4.280 ;
        RECT 156.590 0.155 158.970 4.280 ;
        RECT 159.810 0.155 162.190 4.280 ;
        RECT 163.030 0.155 165.410 4.280 ;
        RECT 166.250 0.155 168.630 4.280 ;
        RECT 169.470 0.155 171.850 4.280 ;
        RECT 172.690 0.155 175.070 4.280 ;
        RECT 175.910 0.155 178.290 4.280 ;
        RECT 179.130 0.155 181.510 4.280 ;
        RECT 182.350 0.155 184.730 4.280 ;
        RECT 185.570 0.155 187.950 4.280 ;
        RECT 188.790 0.155 191.170 4.280 ;
        RECT 192.010 0.155 194.390 4.280 ;
        RECT 195.230 0.155 197.610 4.280 ;
        RECT 198.450 0.155 200.830 4.280 ;
        RECT 201.670 0.155 204.050 4.280 ;
        RECT 204.890 0.155 207.270 4.280 ;
        RECT 208.110 0.155 210.490 4.280 ;
        RECT 211.330 0.155 213.710 4.280 ;
        RECT 214.550 0.155 216.930 4.280 ;
        RECT 217.770 0.155 220.150 4.280 ;
        RECT 220.990 0.155 223.370 4.280 ;
        RECT 224.210 0.155 226.590 4.280 ;
        RECT 227.430 0.155 229.810 4.280 ;
        RECT 230.650 0.155 233.030 4.280 ;
        RECT 233.870 0.155 236.250 4.280 ;
        RECT 237.090 0.155 239.470 4.280 ;
        RECT 240.310 0.155 242.690 4.280 ;
        RECT 243.530 0.155 245.910 4.280 ;
        RECT 246.750 0.155 249.130 4.280 ;
        RECT 249.970 0.155 252.350 4.280 ;
        RECT 253.190 0.155 255.570 4.280 ;
        RECT 256.410 0.155 258.790 4.280 ;
        RECT 259.630 0.155 262.010 4.280 ;
        RECT 262.850 0.155 265.230 4.280 ;
        RECT 266.070 0.155 268.450 4.280 ;
        RECT 269.290 0.155 271.670 4.280 ;
        RECT 272.510 0.155 274.890 4.280 ;
        RECT 275.730 0.155 278.110 4.280 ;
        RECT 278.950 0.155 281.330 4.280 ;
        RECT 282.170 0.155 284.550 4.280 ;
        RECT 285.390 0.155 287.770 4.280 ;
        RECT 288.610 0.155 290.990 4.280 ;
        RECT 291.830 0.155 294.210 4.280 ;
        RECT 295.050 0.155 297.430 4.280 ;
        RECT 298.270 0.155 300.650 4.280 ;
        RECT 301.490 0.155 303.870 4.280 ;
        RECT 304.710 0.155 307.090 4.280 ;
        RECT 307.930 0.155 310.310 4.280 ;
        RECT 311.150 0.155 313.530 4.280 ;
        RECT 314.370 0.155 316.750 4.280 ;
        RECT 317.590 0.155 319.970 4.280 ;
        RECT 320.810 0.155 323.190 4.280 ;
        RECT 324.030 0.155 326.410 4.280 ;
        RECT 327.250 0.155 329.630 4.280 ;
        RECT 330.470 0.155 332.850 4.280 ;
        RECT 333.690 0.155 336.070 4.280 ;
        RECT 336.910 0.155 339.290 4.280 ;
        RECT 340.130 0.155 342.510 4.280 ;
        RECT 343.350 0.155 345.730 4.280 ;
        RECT 346.570 0.155 348.950 4.280 ;
        RECT 349.790 0.155 352.170 4.280 ;
        RECT 353.010 0.155 355.390 4.280 ;
        RECT 356.230 0.155 358.610 4.280 ;
        RECT 359.450 0.155 361.830 4.280 ;
        RECT 362.670 0.155 365.050 4.280 ;
        RECT 365.890 0.155 368.270 4.280 ;
        RECT 369.110 0.155 371.490 4.280 ;
        RECT 372.330 0.155 374.710 4.280 ;
        RECT 375.550 0.155 377.930 4.280 ;
        RECT 378.770 0.155 381.150 4.280 ;
        RECT 381.990 0.155 384.370 4.280 ;
        RECT 385.210 0.155 387.590 4.280 ;
        RECT 388.430 0.155 390.810 4.280 ;
        RECT 391.650 0.155 394.030 4.280 ;
        RECT 394.870 0.155 397.250 4.280 ;
        RECT 398.090 0.155 400.470 4.280 ;
        RECT 401.310 0.155 403.690 4.280 ;
        RECT 404.530 0.155 406.910 4.280 ;
        RECT 407.750 0.155 410.130 4.280 ;
        RECT 410.970 0.155 413.350 4.280 ;
        RECT 414.190 0.155 416.570 4.280 ;
        RECT 417.410 0.155 419.790 4.280 ;
        RECT 420.630 0.155 423.010 4.280 ;
        RECT 423.850 0.155 426.230 4.280 ;
        RECT 427.070 0.155 429.450 4.280 ;
        RECT 430.290 0.155 432.670 4.280 ;
        RECT 433.510 0.155 435.890 4.280 ;
        RECT 436.730 0.155 439.110 4.280 ;
        RECT 439.950 0.155 442.330 4.280 ;
        RECT 443.170 0.155 445.550 4.280 ;
        RECT 446.390 0.155 448.770 4.280 ;
        RECT 449.610 0.155 451.990 4.280 ;
        RECT 452.830 0.155 455.210 4.280 ;
        RECT 456.050 0.155 458.430 4.280 ;
        RECT 459.270 0.155 461.650 4.280 ;
        RECT 462.490 0.155 464.870 4.280 ;
        RECT 465.710 0.155 468.090 4.280 ;
        RECT 468.930 0.155 471.310 4.280 ;
        RECT 472.150 0.155 474.530 4.280 ;
        RECT 475.370 0.155 477.750 4.280 ;
        RECT 478.590 0.155 480.970 4.280 ;
        RECT 481.810 0.155 484.190 4.280 ;
        RECT 485.030 0.155 487.410 4.280 ;
        RECT 488.250 0.155 490.630 4.280 ;
        RECT 491.470 0.155 493.850 4.280 ;
        RECT 494.690 0.155 497.070 4.280 ;
        RECT 497.910 0.155 500.290 4.280 ;
        RECT 501.130 0.155 503.510 4.280 ;
        RECT 504.350 0.155 506.730 4.280 ;
        RECT 507.570 0.155 509.950 4.280 ;
        RECT 510.790 0.155 513.170 4.280 ;
        RECT 514.010 0.155 516.390 4.280 ;
        RECT 517.230 0.155 519.610 4.280 ;
        RECT 520.450 0.155 522.830 4.280 ;
        RECT 523.670 0.155 526.050 4.280 ;
        RECT 526.890 0.155 529.270 4.280 ;
        RECT 530.110 0.155 532.490 4.280 ;
        RECT 533.330 0.155 535.710 4.280 ;
        RECT 536.550 0.155 538.930 4.280 ;
        RECT 539.770 0.155 542.150 4.280 ;
        RECT 542.990 0.155 545.370 4.280 ;
        RECT 546.210 0.155 548.590 4.280 ;
        RECT 549.430 0.155 551.810 4.280 ;
        RECT 552.650 0.155 555.030 4.280 ;
        RECT 555.870 0.155 558.250 4.280 ;
        RECT 559.090 0.155 561.470 4.280 ;
        RECT 562.310 0.155 564.690 4.280 ;
        RECT 565.530 0.155 567.910 4.280 ;
        RECT 568.750 0.155 571.130 4.280 ;
        RECT 571.970 0.155 574.350 4.280 ;
        RECT 575.190 0.155 577.570 4.280 ;
        RECT 578.410 0.155 580.790 4.280 ;
        RECT 581.630 0.155 584.010 4.280 ;
        RECT 584.850 0.155 587.230 4.280 ;
        RECT 588.070 0.155 590.450 4.280 ;
        RECT 591.290 0.155 593.670 4.280 ;
        RECT 594.510 0.155 596.890 4.280 ;
        RECT 597.730 0.155 600.110 4.280 ;
        RECT 600.950 0.155 603.330 4.280 ;
        RECT 604.170 0.155 606.550 4.280 ;
        RECT 607.390 0.155 609.770 4.280 ;
        RECT 610.610 0.155 612.990 4.280 ;
        RECT 613.830 0.155 616.210 4.280 ;
        RECT 617.050 0.155 619.430 4.280 ;
        RECT 620.270 0.155 622.650 4.280 ;
        RECT 623.490 0.155 625.870 4.280 ;
        RECT 626.710 0.155 629.090 4.280 ;
        RECT 629.930 0.155 632.310 4.280 ;
        RECT 633.150 0.155 635.530 4.280 ;
        RECT 636.370 0.155 638.750 4.280 ;
        RECT 639.590 0.155 641.970 4.280 ;
        RECT 642.810 0.155 645.190 4.280 ;
        RECT 646.030 0.155 648.410 4.280 ;
        RECT 649.250 0.155 651.630 4.280 ;
        RECT 652.470 0.155 654.850 4.280 ;
        RECT 655.690 0.155 658.070 4.280 ;
        RECT 658.910 0.155 661.290 4.280 ;
        RECT 662.130 0.155 664.510 4.280 ;
        RECT 665.350 0.155 667.730 4.280 ;
        RECT 668.570 0.155 670.950 4.280 ;
        RECT 671.790 0.155 674.170 4.280 ;
        RECT 675.010 0.155 677.390 4.280 ;
        RECT 678.230 0.155 680.610 4.280 ;
        RECT 681.450 0.155 683.830 4.280 ;
        RECT 684.670 0.155 687.050 4.280 ;
        RECT 687.890 0.155 690.270 4.280 ;
        RECT 691.110 0.155 693.490 4.280 ;
        RECT 694.330 0.155 696.710 4.280 ;
        RECT 697.550 0.155 699.930 4.280 ;
        RECT 700.770 0.155 703.150 4.280 ;
        RECT 703.990 0.155 706.370 4.280 ;
        RECT 707.210 0.155 709.590 4.280 ;
        RECT 710.430 0.155 712.810 4.280 ;
        RECT 713.650 0.155 716.030 4.280 ;
        RECT 716.870 0.155 719.250 4.280 ;
        RECT 720.090 0.155 722.470 4.280 ;
        RECT 723.310 0.155 725.690 4.280 ;
        RECT 726.530 0.155 728.910 4.280 ;
        RECT 729.750 0.155 732.130 4.280 ;
        RECT 732.970 0.155 735.350 4.280 ;
        RECT 736.190 0.155 738.570 4.280 ;
        RECT 739.410 0.155 741.790 4.280 ;
        RECT 742.630 0.155 745.010 4.280 ;
        RECT 745.850 0.155 748.230 4.280 ;
        RECT 749.070 0.155 751.450 4.280 ;
        RECT 752.290 0.155 754.670 4.280 ;
        RECT 755.510 0.155 757.890 4.280 ;
        RECT 758.730 0.155 761.110 4.280 ;
      LAYER met3 ;
        RECT 1.905 750.400 759.815 764.825 ;
        RECT 4.400 749.000 759.815 750.400 ;
        RECT 1.905 746.320 759.815 749.000 ;
        RECT 1.905 744.920 759.415 746.320 ;
        RECT 1.905 732.720 759.815 744.920 ;
        RECT 4.400 731.320 759.815 732.720 ;
        RECT 1.905 730.000 759.815 731.320 ;
        RECT 1.905 728.600 759.415 730.000 ;
        RECT 1.905 715.040 759.815 728.600 ;
        RECT 4.400 713.680 759.815 715.040 ;
        RECT 4.400 713.640 759.415 713.680 ;
        RECT 1.905 712.280 759.415 713.640 ;
        RECT 1.905 697.360 759.815 712.280 ;
        RECT 4.400 695.960 759.415 697.360 ;
        RECT 1.905 681.040 759.815 695.960 ;
        RECT 1.905 679.680 759.415 681.040 ;
        RECT 4.400 679.640 759.415 679.680 ;
        RECT 4.400 678.280 759.815 679.640 ;
        RECT 1.905 664.720 759.815 678.280 ;
        RECT 1.905 663.320 759.415 664.720 ;
        RECT 1.905 662.000 759.815 663.320 ;
        RECT 4.400 660.600 759.815 662.000 ;
        RECT 1.905 648.400 759.815 660.600 ;
        RECT 1.905 647.000 759.415 648.400 ;
        RECT 1.905 644.320 759.815 647.000 ;
        RECT 4.400 642.920 759.815 644.320 ;
        RECT 1.905 632.080 759.815 642.920 ;
        RECT 1.905 630.680 759.415 632.080 ;
        RECT 1.905 626.640 759.815 630.680 ;
        RECT 4.400 625.240 759.815 626.640 ;
        RECT 1.905 615.760 759.815 625.240 ;
        RECT 1.905 614.360 759.415 615.760 ;
        RECT 1.905 608.960 759.815 614.360 ;
        RECT 4.400 607.560 759.815 608.960 ;
        RECT 1.905 599.440 759.815 607.560 ;
        RECT 1.905 598.040 759.415 599.440 ;
        RECT 1.905 591.280 759.815 598.040 ;
        RECT 4.400 589.880 759.815 591.280 ;
        RECT 1.905 583.120 759.815 589.880 ;
        RECT 1.905 581.720 759.415 583.120 ;
        RECT 1.905 573.600 759.815 581.720 ;
        RECT 4.400 572.200 759.815 573.600 ;
        RECT 1.905 566.800 759.815 572.200 ;
        RECT 1.905 565.400 759.415 566.800 ;
        RECT 1.905 555.920 759.815 565.400 ;
        RECT 4.400 554.520 759.815 555.920 ;
        RECT 1.905 550.480 759.815 554.520 ;
        RECT 1.905 549.080 759.415 550.480 ;
        RECT 1.905 538.240 759.815 549.080 ;
        RECT 4.400 536.840 759.815 538.240 ;
        RECT 1.905 534.160 759.815 536.840 ;
        RECT 1.905 532.760 759.415 534.160 ;
        RECT 1.905 520.560 759.815 532.760 ;
        RECT 4.400 519.160 759.815 520.560 ;
        RECT 1.905 517.840 759.815 519.160 ;
        RECT 1.905 516.440 759.415 517.840 ;
        RECT 1.905 502.880 759.815 516.440 ;
        RECT 4.400 501.520 759.815 502.880 ;
        RECT 4.400 501.480 759.415 501.520 ;
        RECT 1.905 500.120 759.415 501.480 ;
        RECT 1.905 485.200 759.815 500.120 ;
        RECT 4.400 483.800 759.415 485.200 ;
        RECT 1.905 468.880 759.815 483.800 ;
        RECT 1.905 467.520 759.415 468.880 ;
        RECT 4.400 467.480 759.415 467.520 ;
        RECT 4.400 466.120 759.815 467.480 ;
        RECT 1.905 452.560 759.815 466.120 ;
        RECT 1.905 451.160 759.415 452.560 ;
        RECT 1.905 449.840 759.815 451.160 ;
        RECT 4.400 448.440 759.815 449.840 ;
        RECT 1.905 436.240 759.815 448.440 ;
        RECT 1.905 434.840 759.415 436.240 ;
        RECT 1.905 432.160 759.815 434.840 ;
        RECT 4.400 430.760 759.815 432.160 ;
        RECT 1.905 419.920 759.815 430.760 ;
        RECT 1.905 418.520 759.415 419.920 ;
        RECT 1.905 414.480 759.815 418.520 ;
        RECT 4.400 413.080 759.815 414.480 ;
        RECT 1.905 403.600 759.815 413.080 ;
        RECT 1.905 402.200 759.415 403.600 ;
        RECT 1.905 396.800 759.815 402.200 ;
        RECT 4.400 395.400 759.815 396.800 ;
        RECT 1.905 387.280 759.815 395.400 ;
        RECT 1.905 385.880 759.415 387.280 ;
        RECT 1.905 379.120 759.815 385.880 ;
        RECT 4.400 377.720 759.815 379.120 ;
        RECT 1.905 370.960 759.815 377.720 ;
        RECT 1.905 369.560 759.415 370.960 ;
        RECT 1.905 361.440 759.815 369.560 ;
        RECT 4.400 360.040 759.815 361.440 ;
        RECT 1.905 354.640 759.815 360.040 ;
        RECT 1.905 353.240 759.415 354.640 ;
        RECT 1.905 343.760 759.815 353.240 ;
        RECT 4.400 342.360 759.815 343.760 ;
        RECT 1.905 338.320 759.815 342.360 ;
        RECT 1.905 336.920 759.415 338.320 ;
        RECT 1.905 326.080 759.815 336.920 ;
        RECT 4.400 324.680 759.815 326.080 ;
        RECT 1.905 322.000 759.815 324.680 ;
        RECT 1.905 320.600 759.415 322.000 ;
        RECT 1.905 308.400 759.815 320.600 ;
        RECT 4.400 307.000 759.815 308.400 ;
        RECT 1.905 305.680 759.815 307.000 ;
        RECT 1.905 304.280 759.415 305.680 ;
        RECT 1.905 290.720 759.815 304.280 ;
        RECT 4.400 289.360 759.815 290.720 ;
        RECT 4.400 289.320 759.415 289.360 ;
        RECT 1.905 287.960 759.415 289.320 ;
        RECT 1.905 273.040 759.815 287.960 ;
        RECT 4.400 271.640 759.415 273.040 ;
        RECT 1.905 256.720 759.815 271.640 ;
        RECT 1.905 255.360 759.415 256.720 ;
        RECT 4.400 255.320 759.415 255.360 ;
        RECT 4.400 253.960 759.815 255.320 ;
        RECT 1.905 240.400 759.815 253.960 ;
        RECT 1.905 239.000 759.415 240.400 ;
        RECT 1.905 237.680 759.815 239.000 ;
        RECT 4.400 236.280 759.815 237.680 ;
        RECT 1.905 224.080 759.815 236.280 ;
        RECT 1.905 222.680 759.415 224.080 ;
        RECT 1.905 220.000 759.815 222.680 ;
        RECT 4.400 218.600 759.815 220.000 ;
        RECT 1.905 207.760 759.815 218.600 ;
        RECT 1.905 206.360 759.415 207.760 ;
        RECT 1.905 202.320 759.815 206.360 ;
        RECT 4.400 200.920 759.815 202.320 ;
        RECT 1.905 191.440 759.815 200.920 ;
        RECT 1.905 190.040 759.415 191.440 ;
        RECT 1.905 184.640 759.815 190.040 ;
        RECT 4.400 183.240 759.815 184.640 ;
        RECT 1.905 175.120 759.815 183.240 ;
        RECT 1.905 173.720 759.415 175.120 ;
        RECT 1.905 166.960 759.815 173.720 ;
        RECT 4.400 165.560 759.815 166.960 ;
        RECT 1.905 158.800 759.815 165.560 ;
        RECT 1.905 157.400 759.415 158.800 ;
        RECT 1.905 149.280 759.815 157.400 ;
        RECT 4.400 147.880 759.815 149.280 ;
        RECT 1.905 142.480 759.815 147.880 ;
        RECT 1.905 141.080 759.415 142.480 ;
        RECT 1.905 131.600 759.815 141.080 ;
        RECT 4.400 130.200 759.815 131.600 ;
        RECT 1.905 126.160 759.815 130.200 ;
        RECT 1.905 124.760 759.415 126.160 ;
        RECT 1.905 113.920 759.815 124.760 ;
        RECT 4.400 112.520 759.815 113.920 ;
        RECT 1.905 109.840 759.815 112.520 ;
        RECT 1.905 108.440 759.415 109.840 ;
        RECT 1.905 96.240 759.815 108.440 ;
        RECT 4.400 94.840 759.815 96.240 ;
        RECT 1.905 93.520 759.815 94.840 ;
        RECT 1.905 92.120 759.415 93.520 ;
        RECT 1.905 78.560 759.815 92.120 ;
        RECT 4.400 77.200 759.815 78.560 ;
        RECT 4.400 77.160 759.415 77.200 ;
        RECT 1.905 75.800 759.415 77.160 ;
        RECT 1.905 60.880 759.815 75.800 ;
        RECT 4.400 59.480 759.415 60.880 ;
        RECT 1.905 44.560 759.815 59.480 ;
        RECT 1.905 43.200 759.415 44.560 ;
        RECT 4.400 43.160 759.415 43.200 ;
        RECT 4.400 41.800 759.815 43.160 ;
        RECT 1.905 28.240 759.815 41.800 ;
        RECT 1.905 26.840 759.415 28.240 ;
        RECT 1.905 25.520 759.815 26.840 ;
        RECT 4.400 24.120 759.815 25.520 ;
        RECT 1.905 0.175 759.815 24.120 ;
      LAYER met4 ;
        RECT 23.295 762.240 709.945 764.825 ;
        RECT 23.295 10.240 97.440 762.240 ;
        RECT 99.840 10.240 174.240 762.240 ;
        RECT 176.640 10.240 251.040 762.240 ;
        RECT 253.440 10.240 327.840 762.240 ;
        RECT 330.240 10.240 404.640 762.240 ;
        RECT 407.040 10.240 481.440 762.240 ;
        RECT 483.840 10.240 558.240 762.240 ;
        RECT 560.640 10.240 635.040 762.240 ;
        RECT 637.440 10.240 709.945 762.240 ;
        RECT 23.295 0.175 709.945 10.240 ;
  END
END mcu_top
END LIBRARY

